VERSION 5.8 ;
BUSBITCHARS "[]" ;
DIVIDERCHAR "/" ;
UNITS
    DATABASE MICRONS 1000 ;
END UNITS

VIA ino_data_cache_via1_2_1000_440_1_2_410_410
  VIARULE via1Array ;
  CUTSIZE 0.19 0.19 ;
  LAYERS Metal1 Via1 Metal2 ;
  CUTSPACING 0.22 0.22 ;
  ENCLOSURE 0.05 0.125 0.005 0.05 ;
  ROWCOL 1 2 ;
END ino_data_cache_via1_2_1000_440_1_2_410_410

VIA ino_data_cache_via2_3_1000_440_1_2_410_410
  VIARULE via2Array ;
  CUTSIZE 0.19 0.19 ;
  LAYERS Metal2 Via2 Metal3 ;
  CUTSPACING 0.22 0.22 ;
  ENCLOSURE 0.005 0.05 0.05 0.005 ;
  ROWCOL 1 2 ;
END ino_data_cache_via2_3_1000_440_1_2_410_410

VIA ino_data_cache_via3_4_1000_440_1_2_410_410
  VIARULE via3Array ;
  CUTSIZE 0.19 0.19 ;
  LAYERS Metal3 Via3 Metal4 ;
  CUTSPACING 0.22 0.22 ;
  ENCLOSURE 0.05 0.005 0.2 0.05 ;
  ROWCOL 1 2 ;
END ino_data_cache_via3_4_1000_440_1_2_410_410

VIA ino_data_cache_via4_5_1000_2000_1_1_840_840
  VIARULE viaTop1Array ;
  CUTSIZE 0.42 0.42 ;
  LAYERS Metal4 TopVia1 TopMetal1 ;
  CUTSPACING 0.42 0.42 ;
  ENCLOSURE 0.29 0.1 0.42 0.79 ;
END ino_data_cache_via4_5_1000_2000_1_1_840_840

VIA ino_data_cache_via4_5_2810_2000_1_2_840_840
  VIARULE viaTop1Array ;
  CUTSIZE 0.42 0.42 ;
  LAYERS Metal4 TopVia1 TopMetal1 ;
  CUTSPACING 0.42 0.42 ;
  ENCLOSURE 0.775 0.79 0.42 0.79 ;
  ROWCOL 1 2 ;
END ino_data_cache_via4_5_2810_2000_1_2_840_840

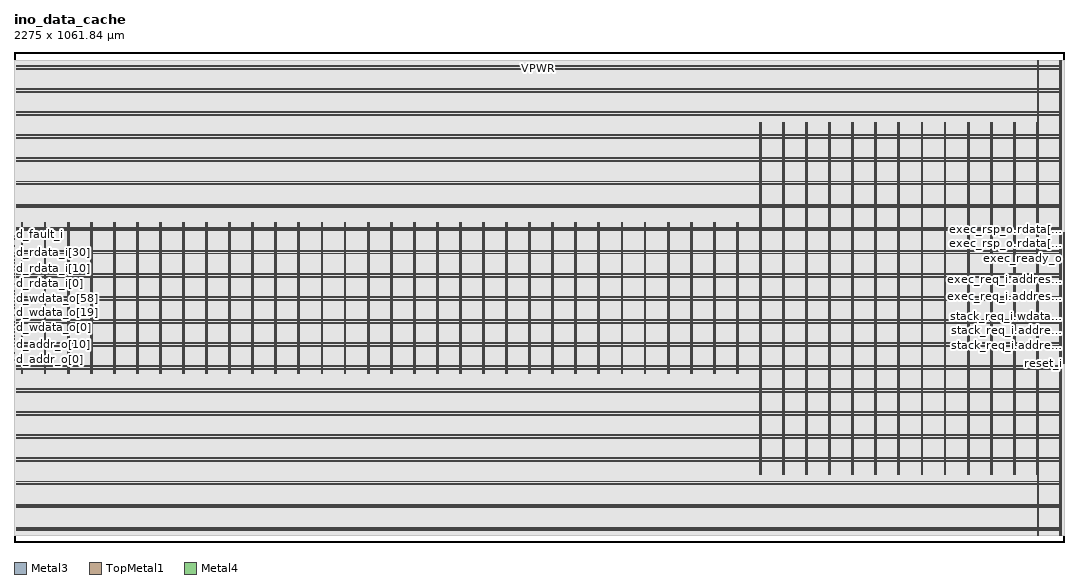
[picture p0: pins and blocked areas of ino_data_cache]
MACRO ino_data_cache
  FOREIGN ino_data_cache 0 0 ;
  CLASS BLOCK ;
  SIZE 2275 BY 1061.84 ;
  PIN clk_i
    DIRECTION INPUT ;
    USE SIGNAL ;
    PORT
      LAYER Metal3 ;
        RECT  2274.6 387.46 2275 387.86 ;
    END
  END clk_i
  PIN d_addr_o[0]
    DIRECTION OUTPUT ;
    USE SIGNAL ;
    PORT
      LAYER Metal3 ;
        RECT  0 394.18 0.4 394.58 ;
    END
  END d_addr_o[0]
  PIN d_addr_o[10]
    DIRECTION OUTPUT ;
    USE SIGNAL ;
    PORT
      LAYER Metal3 ;
        RECT  0 410.98 0.4 411.38 ;
    END
  END d_addr_o[10]
  PIN d_addr_o[11]
    DIRECTION OUTPUT ;
    USE SIGNAL ;
    PORT
      LAYER Metal3 ;
        RECT  0 412.66 0.4 413.06 ;
    END
  END d_addr_o[11]
  PIN d_addr_o[12]
    DIRECTION OUTPUT ;
    USE SIGNAL ;
    PORT
      LAYER Metal3 ;
        RECT  0 414.34 0.4 414.74 ;
    END
  END d_addr_o[12]
  PIN d_addr_o[13]
    DIRECTION OUTPUT ;
    USE SIGNAL ;
    PORT
      LAYER Metal3 ;
        RECT  0 416.02 0.4 416.42 ;
    END
  END d_addr_o[13]
  PIN d_addr_o[14]
    DIRECTION OUTPUT ;
    USE SIGNAL ;
    PORT
      LAYER Metal3 ;
        RECT  0 417.7 0.4 418.1 ;
    END
  END d_addr_o[14]
  PIN d_addr_o[15]
    DIRECTION OUTPUT ;
    USE SIGNAL ;
    PORT
      LAYER Metal3 ;
        RECT  0 419.38 0.4 419.78 ;
    END
  END d_addr_o[15]
  PIN d_addr_o[16]
    DIRECTION OUTPUT ;
    USE SIGNAL ;
    PORT
      LAYER Metal3 ;
        RECT  0 421.06 0.4 421.46 ;
    END
  END d_addr_o[16]
  PIN d_addr_o[17]
    DIRECTION OUTPUT ;
    USE SIGNAL ;
    PORT
      LAYER Metal3 ;
        RECT  0 422.74 0.4 423.14 ;
    END
  END d_addr_o[17]
  PIN d_addr_o[18]
    DIRECTION OUTPUT ;
    USE SIGNAL ;
    PORT
      LAYER Metal3 ;
        RECT  0 424.42 0.4 424.82 ;
    END
  END d_addr_o[18]
  PIN d_addr_o[19]
    DIRECTION OUTPUT ;
    USE SIGNAL ;
    PORT
      LAYER Metal3 ;
        RECT  0 426.1 0.4 426.5 ;
    END
  END d_addr_o[19]
  PIN d_addr_o[1]
    DIRECTION OUTPUT ;
    USE SIGNAL ;
    PORT
      LAYER Metal3 ;
        RECT  0 395.86 0.4 396.26 ;
    END
  END d_addr_o[1]
  PIN d_addr_o[20]
    DIRECTION OUTPUT ;
    USE SIGNAL ;
    PORT
      LAYER Metal3 ;
        RECT  0 427.78 0.4 428.18 ;
    END
  END d_addr_o[20]
  PIN d_addr_o[21]
    DIRECTION OUTPUT ;
    USE SIGNAL ;
    PORT
      LAYER Metal3 ;
        RECT  0 429.46 0.4 429.86 ;
    END
  END d_addr_o[21]
  PIN d_addr_o[22]
    DIRECTION OUTPUT ;
    USE SIGNAL ;
    PORT
      LAYER Metal3 ;
        RECT  0 431.14 0.4 431.54 ;
    END
  END d_addr_o[22]
  PIN d_addr_o[23]
    DIRECTION OUTPUT ;
    USE SIGNAL ;
    PORT
      LAYER Metal3 ;
        RECT  0 432.82 0.4 433.22 ;
    END
  END d_addr_o[23]
  PIN d_addr_o[24]
    DIRECTION OUTPUT ;
    USE SIGNAL ;
    PORT
      LAYER Metal3 ;
        RECT  0 434.5 0.4 434.9 ;
    END
  END d_addr_o[24]
  PIN d_addr_o[25]
    DIRECTION OUTPUT ;
    USE SIGNAL ;
    PORT
      LAYER Metal3 ;
        RECT  0 436.18 0.4 436.58 ;
    END
  END d_addr_o[25]
  PIN d_addr_o[26]
    DIRECTION OUTPUT ;
    USE SIGNAL ;
    PORT
      LAYER Metal3 ;
        RECT  0 437.86 0.4 438.26 ;
    END
  END d_addr_o[26]
  PIN d_addr_o[27]
    DIRECTION OUTPUT ;
    USE SIGNAL ;
    PORT
      LAYER Metal3 ;
        RECT  0 439.54 0.4 439.94 ;
    END
  END d_addr_o[27]
  PIN d_addr_o[28]
    DIRECTION OUTPUT ;
    USE SIGNAL ;
    PORT
      LAYER Metal3 ;
        RECT  0 441.22 0.4 441.62 ;
    END
  END d_addr_o[28]
  PIN d_addr_o[29]
    DIRECTION OUTPUT ;
    USE SIGNAL ;
    PORT
      LAYER Metal3 ;
        RECT  0 442.9 0.4 443.3 ;
    END
  END d_addr_o[29]
  PIN d_addr_o[2]
    DIRECTION OUTPUT ;
    USE SIGNAL ;
    PORT
      LAYER Metal3 ;
        RECT  0 397.54 0.4 397.94 ;
    END
  END d_addr_o[2]
  PIN d_addr_o[30]
    DIRECTION OUTPUT ;
    USE SIGNAL ;
    PORT
      LAYER Metal3 ;
        RECT  0 444.58 0.4 444.98 ;
    END
  END d_addr_o[30]
  PIN d_addr_o[31]
    DIRECTION OUTPUT ;
    USE SIGNAL ;
    PORT
      LAYER Metal3 ;
        RECT  0 446.26 0.4 446.66 ;
    END
  END d_addr_o[31]
  PIN d_addr_o[3]
    DIRECTION OUTPUT ;
    USE SIGNAL ;
    PORT
      LAYER Metal3 ;
        RECT  0 399.22 0.4 399.62 ;
    END
  END d_addr_o[3]
  PIN d_addr_o[4]
    DIRECTION OUTPUT ;
    USE SIGNAL ;
    PORT
      LAYER Metal3 ;
        RECT  0 400.9 0.4 401.3 ;
    END
  END d_addr_o[4]
  PIN d_addr_o[5]
    DIRECTION OUTPUT ;
    USE SIGNAL ;
    PORT
      LAYER Metal3 ;
        RECT  0 402.58 0.4 402.98 ;
    END
  END d_addr_o[5]
  PIN d_addr_o[6]
    DIRECTION OUTPUT ;
    USE SIGNAL ;
    PORT
      LAYER Metal3 ;
        RECT  0 404.26 0.4 404.66 ;
    END
  END d_addr_o[6]
  PIN d_addr_o[7]
    DIRECTION OUTPUT ;
    USE SIGNAL ;
    PORT
      LAYER Metal3 ;
        RECT  0 405.94 0.4 406.34 ;
    END
  END d_addr_o[7]
  PIN d_addr_o[8]
    DIRECTION OUTPUT ;
    USE SIGNAL ;
    PORT
      LAYER Metal3 ;
        RECT  0 407.62 0.4 408.02 ;
    END
  END d_addr_o[8]
  PIN d_addr_o[9]
    DIRECTION OUTPUT ;
    USE SIGNAL ;
    PORT
      LAYER Metal3 ;
        RECT  0 409.3 0.4 409.7 ;
    END
  END d_addr_o[9]
  PIN d_fault_i
    DIRECTION INPUT ;
    USE SIGNAL ;
    PORT
      LAYER Metal3 ;
        RECT  0 666.34 0.4 666.74 ;
    END
  END d_fault_i
  PIN d_rdata_i[0]
    DIRECTION INPUT ;
    USE SIGNAL ;
    PORT
      LAYER Metal3 ;
        RECT  0 558.82 0.4 559.22 ;
    END
  END d_rdata_i[0]
  PIN d_rdata_i[10]
    DIRECTION INPUT ;
    USE SIGNAL ;
    PORT
      LAYER Metal3 ;
        RECT  0 575.62 0.4 576.02 ;
    END
  END d_rdata_i[10]
  PIN d_rdata_i[11]
    DIRECTION INPUT ;
    USE SIGNAL ;
    PORT
      LAYER Metal3 ;
        RECT  0 577.3 0.4 577.7 ;
    END
  END d_rdata_i[11]
  PIN d_rdata_i[12]
    DIRECTION INPUT ;
    USE SIGNAL ;
    PORT
      LAYER Metal3 ;
        RECT  0 578.98 0.4 579.38 ;
    END
  END d_rdata_i[12]
  PIN d_rdata_i[13]
    DIRECTION INPUT ;
    USE SIGNAL ;
    PORT
      LAYER Metal3 ;
        RECT  0 580.66 0.4 581.06 ;
    END
  END d_rdata_i[13]
  PIN d_rdata_i[14]
    DIRECTION INPUT ;
    USE SIGNAL ;
    PORT
      LAYER Metal3 ;
        RECT  0 582.34 0.4 582.74 ;
    END
  END d_rdata_i[14]
  PIN d_rdata_i[15]
    DIRECTION INPUT ;
    USE SIGNAL ;
    PORT
      LAYER Metal3 ;
        RECT  0 584.02 0.4 584.42 ;
    END
  END d_rdata_i[15]
  PIN d_rdata_i[16]
    DIRECTION INPUT ;
    USE SIGNAL ;
    PORT
      LAYER Metal3 ;
        RECT  0 585.7 0.4 586.1 ;
    END
  END d_rdata_i[16]
  PIN d_rdata_i[17]
    DIRECTION INPUT ;
    USE SIGNAL ;
    PORT
      LAYER Metal3 ;
        RECT  0 587.38 0.4 587.78 ;
    END
  END d_rdata_i[17]
  PIN d_rdata_i[18]
    DIRECTION INPUT ;
    USE SIGNAL ;
    PORT
      LAYER Metal3 ;
        RECT  0 589.06 0.4 589.46 ;
    END
  END d_rdata_i[18]
  PIN d_rdata_i[19]
    DIRECTION INPUT ;
    USE SIGNAL ;
    PORT
      LAYER Metal3 ;
        RECT  0 590.74 0.4 591.14 ;
    END
  END d_rdata_i[19]
  PIN d_rdata_i[1]
    DIRECTION INPUT ;
    USE SIGNAL ;
    PORT
      LAYER Metal3 ;
        RECT  0 560.5 0.4 560.9 ;
    END
  END d_rdata_i[1]
  PIN d_rdata_i[20]
    DIRECTION INPUT ;
    USE SIGNAL ;
    PORT
      LAYER Metal3 ;
        RECT  0 592.42 0.4 592.82 ;
    END
  END d_rdata_i[20]
  PIN d_rdata_i[21]
    DIRECTION INPUT ;
    USE SIGNAL ;
    PORT
      LAYER Metal3 ;
        RECT  0 594.1 0.4 594.5 ;
    END
  END d_rdata_i[21]
  PIN d_rdata_i[22]
    DIRECTION INPUT ;
    USE SIGNAL ;
    PORT
      LAYER Metal3 ;
        RECT  0 595.78 0.4 596.18 ;
    END
  END d_rdata_i[22]
  PIN d_rdata_i[23]
    DIRECTION INPUT ;
    USE SIGNAL ;
    PORT
      LAYER Metal3 ;
        RECT  0 597.46 0.4 597.86 ;
    END
  END d_rdata_i[23]
  PIN d_rdata_i[24]
    DIRECTION INPUT ;
    USE SIGNAL ;
    PORT
      LAYER Metal3 ;
        RECT  0 599.14 0.4 599.54 ;
    END
  END d_rdata_i[24]
  PIN d_rdata_i[25]
    DIRECTION INPUT ;
    USE SIGNAL ;
    PORT
      LAYER Metal3 ;
        RECT  0 600.82 0.4 601.22 ;
    END
  END d_rdata_i[25]
  PIN d_rdata_i[26]
    DIRECTION INPUT ;
    USE SIGNAL ;
    PORT
      LAYER Metal3 ;
        RECT  0 602.5 0.4 602.9 ;
    END
  END d_rdata_i[26]
  PIN d_rdata_i[27]
    DIRECTION INPUT ;
    USE SIGNAL ;
    PORT
      LAYER Metal3 ;
        RECT  0 604.18 0.4 604.58 ;
    END
  END d_rdata_i[27]
  PIN d_rdata_i[28]
    DIRECTION INPUT ;
    USE SIGNAL ;
    PORT
      LAYER Metal3 ;
        RECT  0 605.86 0.4 606.26 ;
    END
  END d_rdata_i[28]
  PIN d_rdata_i[29]
    DIRECTION INPUT ;
    USE SIGNAL ;
    PORT
      LAYER Metal3 ;
        RECT  0 607.54 0.4 607.94 ;
    END
  END d_rdata_i[29]
  PIN d_rdata_i[2]
    DIRECTION INPUT ;
    USE SIGNAL ;
    PORT
      LAYER Metal3 ;
        RECT  0 562.18 0.4 562.58 ;
    END
  END d_rdata_i[2]
  PIN d_rdata_i[30]
    DIRECTION INPUT ;
    USE SIGNAL ;
    PORT
      LAYER Metal3 ;
        RECT  0 609.22 0.4 609.62 ;
    END
  END d_rdata_i[30]
  PIN d_rdata_i[31]
    DIRECTION INPUT ;
    USE SIGNAL ;
    PORT
      LAYER Metal3 ;
        RECT  0 610.9 0.4 611.3 ;
    END
  END d_rdata_i[31]
  PIN d_rdata_i[32]
    DIRECTION INPUT ;
    USE SIGNAL ;
    PORT
      LAYER Metal3 ;
        RECT  0 612.58 0.4 612.98 ;
    END
  END d_rdata_i[32]
  PIN d_rdata_i[33]
    DIRECTION INPUT ;
    USE SIGNAL ;
    PORT
      LAYER Metal3 ;
        RECT  0 614.26 0.4 614.66 ;
    END
  END d_rdata_i[33]
  PIN d_rdata_i[34]
    DIRECTION INPUT ;
    USE SIGNAL ;
    PORT
      LAYER Metal3 ;
        RECT  0 615.94 0.4 616.34 ;
    END
  END d_rdata_i[34]
  PIN d_rdata_i[35]
    DIRECTION INPUT ;
    USE SIGNAL ;
    PORT
      LAYER Metal3 ;
        RECT  0 617.62 0.4 618.02 ;
    END
  END d_rdata_i[35]
  PIN d_rdata_i[36]
    DIRECTION INPUT ;
    USE SIGNAL ;
    PORT
      LAYER Metal3 ;
        RECT  0 619.3 0.4 619.7 ;
    END
  END d_rdata_i[36]
  PIN d_rdata_i[37]
    DIRECTION INPUT ;
    USE SIGNAL ;
    PORT
      LAYER Metal3 ;
        RECT  0 620.98 0.4 621.38 ;
    END
  END d_rdata_i[37]
  PIN d_rdata_i[38]
    DIRECTION INPUT ;
    USE SIGNAL ;
    PORT
      LAYER Metal3 ;
        RECT  0 622.66 0.4 623.06 ;
    END
  END d_rdata_i[38]
  PIN d_rdata_i[39]
    DIRECTION INPUT ;
    USE SIGNAL ;
    PORT
      LAYER Metal3 ;
        RECT  0 624.34 0.4 624.74 ;
    END
  END d_rdata_i[39]
  PIN d_rdata_i[3]
    DIRECTION INPUT ;
    USE SIGNAL ;
    PORT
      LAYER Metal3 ;
        RECT  0 563.86 0.4 564.26 ;
    END
  END d_rdata_i[3]
  PIN d_rdata_i[40]
    DIRECTION INPUT ;
    USE SIGNAL ;
    PORT
      LAYER Metal3 ;
        RECT  0 626.02 0.4 626.42 ;
    END
  END d_rdata_i[40]
  PIN d_rdata_i[41]
    DIRECTION INPUT ;
    USE SIGNAL ;
    PORT
      LAYER Metal3 ;
        RECT  0 627.7 0.4 628.1 ;
    END
  END d_rdata_i[41]
  PIN d_rdata_i[42]
    DIRECTION INPUT ;
    USE SIGNAL ;
    PORT
      LAYER Metal3 ;
        RECT  0 629.38 0.4 629.78 ;
    END
  END d_rdata_i[42]
  PIN d_rdata_i[43]
    DIRECTION INPUT ;
    USE SIGNAL ;
    PORT
      LAYER Metal3 ;
        RECT  0 631.06 0.4 631.46 ;
    END
  END d_rdata_i[43]
  PIN d_rdata_i[44]
    DIRECTION INPUT ;
    USE SIGNAL ;
    PORT
      LAYER Metal3 ;
        RECT  0 632.74 0.4 633.14 ;
    END
  END d_rdata_i[44]
  PIN d_rdata_i[45]
    DIRECTION INPUT ;
    USE SIGNAL ;
    PORT
      LAYER Metal3 ;
        RECT  0 634.42 0.4 634.82 ;
    END
  END d_rdata_i[45]
  PIN d_rdata_i[46]
    DIRECTION INPUT ;
    USE SIGNAL ;
    PORT
      LAYER Metal3 ;
        RECT  0 636.1 0.4 636.5 ;
    END
  END d_rdata_i[46]
  PIN d_rdata_i[47]
    DIRECTION INPUT ;
    USE SIGNAL ;
    PORT
      LAYER Metal3 ;
        RECT  0 637.78 0.4 638.18 ;
    END
  END d_rdata_i[47]
  PIN d_rdata_i[48]
    DIRECTION INPUT ;
    USE SIGNAL ;
    PORT
      LAYER Metal3 ;
        RECT  0 639.46 0.4 639.86 ;
    END
  END d_rdata_i[48]
  PIN d_rdata_i[49]
    DIRECTION INPUT ;
    USE SIGNAL ;
    PORT
      LAYER Metal3 ;
        RECT  0 641.14 0.4 641.54 ;
    END
  END d_rdata_i[49]
  PIN d_rdata_i[4]
    DIRECTION INPUT ;
    USE SIGNAL ;
    PORT
      LAYER Metal3 ;
        RECT  0 565.54 0.4 565.94 ;
    END
  END d_rdata_i[4]
  PIN d_rdata_i[50]
    DIRECTION INPUT ;
    USE SIGNAL ;
    PORT
      LAYER Metal3 ;
        RECT  0 642.82 0.4 643.22 ;
    END
  END d_rdata_i[50]
  PIN d_rdata_i[51]
    DIRECTION INPUT ;
    USE SIGNAL ;
    PORT
      LAYER Metal3 ;
        RECT  0 644.5 0.4 644.9 ;
    END
  END d_rdata_i[51]
  PIN d_rdata_i[52]
    DIRECTION INPUT ;
    USE SIGNAL ;
    PORT
      LAYER Metal3 ;
        RECT  0 646.18 0.4 646.58 ;
    END
  END d_rdata_i[52]
  PIN d_rdata_i[53]
    DIRECTION INPUT ;
    USE SIGNAL ;
    PORT
      LAYER Metal3 ;
        RECT  0 647.86 0.4 648.26 ;
    END
  END d_rdata_i[53]
  PIN d_rdata_i[54]
    DIRECTION INPUT ;
    USE SIGNAL ;
    PORT
      LAYER Metal3 ;
        RECT  0 649.54 0.4 649.94 ;
    END
  END d_rdata_i[54]
  PIN d_rdata_i[55]
    DIRECTION INPUT ;
    USE SIGNAL ;
    PORT
      LAYER Metal3 ;
        RECT  0 651.22 0.4 651.62 ;
    END
  END d_rdata_i[55]
  PIN d_rdata_i[56]
    DIRECTION INPUT ;
    USE SIGNAL ;
    PORT
      LAYER Metal3 ;
        RECT  0 652.9 0.4 653.3 ;
    END
  END d_rdata_i[56]
  PIN d_rdata_i[57]
    DIRECTION INPUT ;
    USE SIGNAL ;
    PORT
      LAYER Metal3 ;
        RECT  0 654.58 0.4 654.98 ;
    END
  END d_rdata_i[57]
  PIN d_rdata_i[58]
    DIRECTION INPUT ;
    USE SIGNAL ;
    PORT
      LAYER Metal3 ;
        RECT  0 656.26 0.4 656.66 ;
    END
  END d_rdata_i[58]
  PIN d_rdata_i[59]
    DIRECTION INPUT ;
    USE SIGNAL ;
    PORT
      LAYER Metal3 ;
        RECT  0 657.94 0.4 658.34 ;
    END
  END d_rdata_i[59]
  PIN d_rdata_i[5]
    DIRECTION INPUT ;
    USE SIGNAL ;
    PORT
      LAYER Metal3 ;
        RECT  0 567.22 0.4 567.62 ;
    END
  END d_rdata_i[5]
  PIN d_rdata_i[60]
    DIRECTION INPUT ;
    USE SIGNAL ;
    PORT
      LAYER Metal3 ;
        RECT  0 659.62 0.4 660.02 ;
    END
  END d_rdata_i[60]
  PIN d_rdata_i[61]
    DIRECTION INPUT ;
    USE SIGNAL ;
    PORT
      LAYER Metal3 ;
        RECT  0 661.3 0.4 661.7 ;
    END
  END d_rdata_i[61]
  PIN d_rdata_i[62]
    DIRECTION INPUT ;
    USE SIGNAL ;
    PORT
      LAYER Metal3 ;
        RECT  0 662.98 0.4 663.38 ;
    END
  END d_rdata_i[62]
  PIN d_rdata_i[63]
    DIRECTION INPUT ;
    USE SIGNAL ;
    PORT
      LAYER Metal3 ;
        RECT  0 664.66 0.4 665.06 ;
    END
  END d_rdata_i[63]
  PIN d_rdata_i[6]
    DIRECTION INPUT ;
    USE SIGNAL ;
    PORT
      LAYER Metal3 ;
        RECT  0 568.9 0.4 569.3 ;
    END
  END d_rdata_i[6]
  PIN d_rdata_i[7]
    DIRECTION INPUT ;
    USE SIGNAL ;
    PORT
      LAYER Metal3 ;
        RECT  0 570.58 0.4 570.98 ;
    END
  END d_rdata_i[7]
  PIN d_rdata_i[8]
    DIRECTION INPUT ;
    USE SIGNAL ;
    PORT
      LAYER Metal3 ;
        RECT  0 572.26 0.4 572.66 ;
    END
  END d_rdata_i[8]
  PIN d_rdata_i[9]
    DIRECTION INPUT ;
    USE SIGNAL ;
    PORT
      LAYER Metal3 ;
        RECT  0 573.94 0.4 574.34 ;
    END
  END d_rdata_i[9]
  PIN d_ready_i
    DIRECTION INPUT ;
    USE SIGNAL ;
    PORT
      LAYER Metal3 ;
        RECT  0 555.46 0.4 555.86 ;
    END
  END d_ready_i
  PIN d_req_o
    DIRECTION OUTPUT ;
    USE SIGNAL ;
    PORT
      LAYER Metal3 ;
        RECT  0 390.82 0.4 391.22 ;
    END
  END d_req_o
  PIN d_rvalid_i
    DIRECTION INPUT ;
    USE SIGNAL ;
    PORT
      LAYER Metal3 ;
        RECT  0 557.14 0.4 557.54 ;
    END
  END d_rvalid_i
  PIN d_wdata_o[0]
    DIRECTION OUTPUT ;
    USE SIGNAL ;
    PORT
      LAYER Metal3 ;
        RECT  0 447.94 0.4 448.34 ;
    END
  END d_wdata_o[0]
  PIN d_wdata_o[10]
    DIRECTION OUTPUT ;
    USE SIGNAL ;
    PORT
      LAYER Metal3 ;
        RECT  0 464.74 0.4 465.14 ;
    END
  END d_wdata_o[10]
  PIN d_wdata_o[11]
    DIRECTION OUTPUT ;
    USE SIGNAL ;
    PORT
      LAYER Metal3 ;
        RECT  0 466.42 0.4 466.82 ;
    END
  END d_wdata_o[11]
  PIN d_wdata_o[12]
    DIRECTION OUTPUT ;
    USE SIGNAL ;
    PORT
      LAYER Metal3 ;
        RECT  0 468.1 0.4 468.5 ;
    END
  END d_wdata_o[12]
  PIN d_wdata_o[13]
    DIRECTION OUTPUT ;
    USE SIGNAL ;
    PORT
      LAYER Metal3 ;
        RECT  0 469.78 0.4 470.18 ;
    END
  END d_wdata_o[13]
  PIN d_wdata_o[14]
    DIRECTION OUTPUT ;
    USE SIGNAL ;
    PORT
      LAYER Metal3 ;
        RECT  0 471.46 0.4 471.86 ;
    END
  END d_wdata_o[14]
  PIN d_wdata_o[15]
    DIRECTION OUTPUT ;
    USE SIGNAL ;
    PORT
      LAYER Metal3 ;
        RECT  0 473.14 0.4 473.54 ;
    END
  END d_wdata_o[15]
  PIN d_wdata_o[16]
    DIRECTION OUTPUT ;
    USE SIGNAL ;
    PORT
      LAYER Metal3 ;
        RECT  0 474.82 0.4 475.22 ;
    END
  END d_wdata_o[16]
  PIN d_wdata_o[17]
    DIRECTION OUTPUT ;
    USE SIGNAL ;
    PORT
      LAYER Metal3 ;
        RECT  0 476.5 0.4 476.9 ;
    END
  END d_wdata_o[17]
  PIN d_wdata_o[18]
    DIRECTION OUTPUT ;
    USE SIGNAL ;
    PORT
      LAYER Metal3 ;
        RECT  0 478.18 0.4 478.58 ;
    END
  END d_wdata_o[18]
  PIN d_wdata_o[19]
    DIRECTION OUTPUT ;
    USE SIGNAL ;
    PORT
      LAYER Metal3 ;
        RECT  0 479.86 0.4 480.26 ;
    END
  END d_wdata_o[19]
  PIN d_wdata_o[1]
    DIRECTION OUTPUT ;
    USE SIGNAL ;
    PORT
      LAYER Metal3 ;
        RECT  0 449.62 0.4 450.02 ;
    END
  END d_wdata_o[1]
  PIN d_wdata_o[20]
    DIRECTION OUTPUT ;
    USE SIGNAL ;
    PORT
      LAYER Metal3 ;
        RECT  0 481.54 0.4 481.94 ;
    END
  END d_wdata_o[20]
  PIN d_wdata_o[21]
    DIRECTION OUTPUT ;
    USE SIGNAL ;
    PORT
      LAYER Metal3 ;
        RECT  0 483.22 0.4 483.62 ;
    END
  END d_wdata_o[21]
  PIN d_wdata_o[22]
    DIRECTION OUTPUT ;
    USE SIGNAL ;
    PORT
      LAYER Metal3 ;
        RECT  0 484.9 0.4 485.3 ;
    END
  END d_wdata_o[22]
  PIN d_wdata_o[23]
    DIRECTION OUTPUT ;
    USE SIGNAL ;
    PORT
      LAYER Metal3 ;
        RECT  0 486.58 0.4 486.98 ;
    END
  END d_wdata_o[23]
  PIN d_wdata_o[24]
    DIRECTION OUTPUT ;
    USE SIGNAL ;
    PORT
      LAYER Metal3 ;
        RECT  0 488.26 0.4 488.66 ;
    END
  END d_wdata_o[24]
  PIN d_wdata_o[25]
    DIRECTION OUTPUT ;
    USE SIGNAL ;
    PORT
      LAYER Metal3 ;
        RECT  0 489.94 0.4 490.34 ;
    END
  END d_wdata_o[25]
  PIN d_wdata_o[26]
    DIRECTION OUTPUT ;
    USE SIGNAL ;
    PORT
      LAYER Metal3 ;
        RECT  0 491.62 0.4 492.02 ;
    END
  END d_wdata_o[26]
  PIN d_wdata_o[27]
    DIRECTION OUTPUT ;
    USE SIGNAL ;
    PORT
      LAYER Metal3 ;
        RECT  0 493.3 0.4 493.7 ;
    END
  END d_wdata_o[27]
  PIN d_wdata_o[28]
    DIRECTION OUTPUT ;
    USE SIGNAL ;
    PORT
      LAYER Metal3 ;
        RECT  0 494.98 0.4 495.38 ;
    END
  END d_wdata_o[28]
  PIN d_wdata_o[29]
    DIRECTION OUTPUT ;
    USE SIGNAL ;
    PORT
      LAYER Metal3 ;
        RECT  0 496.66 0.4 497.06 ;
    END
  END d_wdata_o[29]
  PIN d_wdata_o[2]
    DIRECTION OUTPUT ;
    USE SIGNAL ;
    PORT
      LAYER Metal3 ;
        RECT  0 451.3 0.4 451.7 ;
    END
  END d_wdata_o[2]
  PIN d_wdata_o[30]
    DIRECTION OUTPUT ;
    USE SIGNAL ;
    PORT
      LAYER Metal3 ;
        RECT  0 498.34 0.4 498.74 ;
    END
  END d_wdata_o[30]
  PIN d_wdata_o[31]
    DIRECTION OUTPUT ;
    USE SIGNAL ;
    PORT
      LAYER Metal3 ;
        RECT  0 500.02 0.4 500.42 ;
    END
  END d_wdata_o[31]
  PIN d_wdata_o[32]
    DIRECTION OUTPUT ;
    USE SIGNAL ;
    PORT
      LAYER Metal3 ;
        RECT  0 501.7 0.4 502.1 ;
    END
  END d_wdata_o[32]
  PIN d_wdata_o[33]
    DIRECTION OUTPUT ;
    USE SIGNAL ;
    PORT
      LAYER Metal3 ;
        RECT  0 503.38 0.4 503.78 ;
    END
  END d_wdata_o[33]
  PIN d_wdata_o[34]
    DIRECTION OUTPUT ;
    USE SIGNAL ;
    PORT
      LAYER Metal3 ;
        RECT  0 505.06 0.4 505.46 ;
    END
  END d_wdata_o[34]
  PIN d_wdata_o[35]
    DIRECTION OUTPUT ;
    USE SIGNAL ;
    PORT
      LAYER Metal3 ;
        RECT  0 506.74 0.4 507.14 ;
    END
  END d_wdata_o[35]
  PIN d_wdata_o[36]
    DIRECTION OUTPUT ;
    USE SIGNAL ;
    PORT
      LAYER Metal3 ;
        RECT  0 508.42 0.4 508.82 ;
    END
  END d_wdata_o[36]
  PIN d_wdata_o[37]
    DIRECTION OUTPUT ;
    USE SIGNAL ;
    PORT
      LAYER Metal3 ;
        RECT  0 510.1 0.4 510.5 ;
    END
  END d_wdata_o[37]
  PIN d_wdata_o[38]
    DIRECTION OUTPUT ;
    USE SIGNAL ;
    PORT
      LAYER Metal3 ;
        RECT  0 511.78 0.4 512.18 ;
    END
  END d_wdata_o[38]
  PIN d_wdata_o[39]
    DIRECTION OUTPUT ;
    USE SIGNAL ;
    PORT
      LAYER Metal3 ;
        RECT  0 513.46 0.4 513.86 ;
    END
  END d_wdata_o[39]
  PIN d_wdata_o[3]
    DIRECTION OUTPUT ;
    USE SIGNAL ;
    PORT
      LAYER Metal3 ;
        RECT  0 452.98 0.4 453.38 ;
    END
  END d_wdata_o[3]
  PIN d_wdata_o[40]
    DIRECTION OUTPUT ;
    USE SIGNAL ;
    PORT
      LAYER Metal3 ;
        RECT  0 515.14 0.4 515.54 ;
    END
  END d_wdata_o[40]
  PIN d_wdata_o[41]
    DIRECTION OUTPUT ;
    USE SIGNAL ;
    PORT
      LAYER Metal3 ;
        RECT  0 516.82 0.4 517.22 ;
    END
  END d_wdata_o[41]
  PIN d_wdata_o[42]
    DIRECTION OUTPUT ;
    USE SIGNAL ;
    PORT
      LAYER Metal3 ;
        RECT  0 518.5 0.4 518.9 ;
    END
  END d_wdata_o[42]
  PIN d_wdata_o[43]
    DIRECTION OUTPUT ;
    USE SIGNAL ;
    PORT
      LAYER Metal3 ;
        RECT  0 520.18 0.4 520.58 ;
    END
  END d_wdata_o[43]
  PIN d_wdata_o[44]
    DIRECTION OUTPUT ;
    USE SIGNAL ;
    PORT
      LAYER Metal3 ;
        RECT  0 521.86 0.4 522.26 ;
    END
  END d_wdata_o[44]
  PIN d_wdata_o[45]
    DIRECTION OUTPUT ;
    USE SIGNAL ;
    PORT
      LAYER Metal3 ;
        RECT  0 523.54 0.4 523.94 ;
    END
  END d_wdata_o[45]
  PIN d_wdata_o[46]
    DIRECTION OUTPUT ;
    USE SIGNAL ;
    PORT
      LAYER Metal3 ;
        RECT  0 525.22 0.4 525.62 ;
    END
  END d_wdata_o[46]
  PIN d_wdata_o[47]
    DIRECTION OUTPUT ;
    USE SIGNAL ;
    PORT
      LAYER Metal3 ;
        RECT  0 526.9 0.4 527.3 ;
    END
  END d_wdata_o[47]
  PIN d_wdata_o[48]
    DIRECTION OUTPUT ;
    USE SIGNAL ;
    PORT
      LAYER Metal3 ;
        RECT  0 528.58 0.4 528.98 ;
    END
  END d_wdata_o[48]
  PIN d_wdata_o[49]
    DIRECTION OUTPUT ;
    USE SIGNAL ;
    PORT
      LAYER Metal3 ;
        RECT  0 530.26 0.4 530.66 ;
    END
  END d_wdata_o[49]
  PIN d_wdata_o[4]
    DIRECTION OUTPUT ;
    USE SIGNAL ;
    PORT
      LAYER Metal3 ;
        RECT  0 454.66 0.4 455.06 ;
    END
  END d_wdata_o[4]
  PIN d_wdata_o[50]
    DIRECTION OUTPUT ;
    USE SIGNAL ;
    PORT
      LAYER Metal3 ;
        RECT  0 531.94 0.4 532.34 ;
    END
  END d_wdata_o[50]
  PIN d_wdata_o[51]
    DIRECTION OUTPUT ;
    USE SIGNAL ;
    PORT
      LAYER Metal3 ;
        RECT  0 533.62 0.4 534.02 ;
    END
  END d_wdata_o[51]
  PIN d_wdata_o[52]
    DIRECTION OUTPUT ;
    USE SIGNAL ;
    PORT
      LAYER Metal3 ;
        RECT  0 535.3 0.4 535.7 ;
    END
  END d_wdata_o[52]
  PIN d_wdata_o[53]
    DIRECTION OUTPUT ;
    USE SIGNAL ;
    PORT
      LAYER Metal3 ;
        RECT  0 536.98 0.4 537.38 ;
    END
  END d_wdata_o[53]
  PIN d_wdata_o[54]
    DIRECTION OUTPUT ;
    USE SIGNAL ;
    PORT
      LAYER Metal3 ;
        RECT  0 538.66 0.4 539.06 ;
    END
  END d_wdata_o[54]
  PIN d_wdata_o[55]
    DIRECTION OUTPUT ;
    USE SIGNAL ;
    PORT
      LAYER Metal3 ;
        RECT  0 540.34 0.4 540.74 ;
    END
  END d_wdata_o[55]
  PIN d_wdata_o[56]
    DIRECTION OUTPUT ;
    USE SIGNAL ;
    PORT
      LAYER Metal3 ;
        RECT  0 542.02 0.4 542.42 ;
    END
  END d_wdata_o[56]
  PIN d_wdata_o[57]
    DIRECTION OUTPUT ;
    USE SIGNAL ;
    PORT
      LAYER Metal3 ;
        RECT  0 543.7 0.4 544.1 ;
    END
  END d_wdata_o[57]
  PIN d_wdata_o[58]
    DIRECTION OUTPUT ;
    USE SIGNAL ;
    PORT
      LAYER Metal3 ;
        RECT  0 545.38 0.4 545.78 ;
    END
  END d_wdata_o[58]
  PIN d_wdata_o[59]
    DIRECTION OUTPUT ;
    USE SIGNAL ;
    PORT
      LAYER Metal3 ;
        RECT  0 547.06 0.4 547.46 ;
    END
  END d_wdata_o[59]
  PIN d_wdata_o[5]
    DIRECTION OUTPUT ;
    USE SIGNAL ;
    PORT
      LAYER Metal3 ;
        RECT  0 456.34 0.4 456.74 ;
    END
  END d_wdata_o[5]
  PIN d_wdata_o[60]
    DIRECTION OUTPUT ;
    USE SIGNAL ;
    PORT
      LAYER Metal3 ;
        RECT  0 548.74 0.4 549.14 ;
    END
  END d_wdata_o[60]
  PIN d_wdata_o[61]
    DIRECTION OUTPUT ;
    USE SIGNAL ;
    PORT
      LAYER Metal3 ;
        RECT  0 550.42 0.4 550.82 ;
    END
  END d_wdata_o[61]
  PIN d_wdata_o[62]
    DIRECTION OUTPUT ;
    USE SIGNAL ;
    PORT
      LAYER Metal3 ;
        RECT  0 552.1 0.4 552.5 ;
    END
  END d_wdata_o[62]
  PIN d_wdata_o[63]
    DIRECTION OUTPUT ;
    USE SIGNAL ;
    PORT
      LAYER Metal3 ;
        RECT  0 553.78 0.4 554.18 ;
    END
  END d_wdata_o[63]
  PIN d_wdata_o[6]
    DIRECTION OUTPUT ;
    USE SIGNAL ;
    PORT
      LAYER Metal3 ;
        RECT  0 458.02 0.4 458.42 ;
    END
  END d_wdata_o[6]
  PIN d_wdata_o[7]
    DIRECTION OUTPUT ;
    USE SIGNAL ;
    PORT
      LAYER Metal3 ;
        RECT  0 459.7 0.4 460.1 ;
    END
  END d_wdata_o[7]
  PIN d_wdata_o[8]
    DIRECTION OUTPUT ;
    USE SIGNAL ;
    PORT
      LAYER Metal3 ;
        RECT  0 461.38 0.4 461.78 ;
    END
  END d_wdata_o[8]
  PIN d_wdata_o[9]
    DIRECTION OUTPUT ;
    USE SIGNAL ;
    PORT
      LAYER Metal3 ;
        RECT  0 463.06 0.4 463.46 ;
    END
  END d_wdata_o[9]
  PIN d_write_o
    DIRECTION OUTPUT ;
    USE SIGNAL ;
    PORT
      LAYER Metal3 ;
        RECT  0 392.5 0.4 392.9 ;
    END
  END d_write_o
  PIN exec_ready_o
    DIRECTION OUTPUT ;
    USE SIGNAL ;
    PORT
      LAYER Metal3 ;
        RECT  2274.6 615.1 2275 615.5 ;
    END
  END exec_ready_o
  PIN exec_req_i.address[0]
    DIRECTION INPUT ;
    USE SIGNAL ;
    PORT
      LAYER Metal3 ;
        RECT  2274.6 532.78 2275 533.18 ;
    END
  END exec_req_i.address[0]
  PIN exec_req_i.address[10]
    DIRECTION INPUT ;
    USE SIGNAL ;
    PORT
      LAYER Metal3 ;
        RECT  2274.6 551.26 2275 551.66 ;
    END
  END exec_req_i.address[10]
  PIN exec_req_i.address[11]
    DIRECTION INPUT ;
    USE SIGNAL ;
    PORT
      LAYER Metal3 ;
        RECT  2274.6 552.94 2275 553.34 ;
    END
  END exec_req_i.address[11]
  PIN exec_req_i.address[12]
    DIRECTION INPUT ;
    USE SIGNAL ;
    PORT
      LAYER Metal3 ;
        RECT  2274.6 554.62 2275 555.02 ;
    END
  END exec_req_i.address[12]
  PIN exec_req_i.address[13]
    DIRECTION INPUT ;
    USE SIGNAL ;
    PORT
      LAYER Metal3 ;
        RECT  2274.6 556.3 2275 556.7 ;
    END
  END exec_req_i.address[13]
  PIN exec_req_i.address[14]
    DIRECTION INPUT ;
    USE SIGNAL ;
    PORT
      LAYER Metal3 ;
        RECT  2274.6 557.98 2275 558.38 ;
    END
  END exec_req_i.address[14]
  PIN exec_req_i.address[15]
    DIRECTION INPUT ;
    USE SIGNAL ;
    PORT
      LAYER Metal3 ;
        RECT  2274.6 559.66 2275 560.06 ;
    END
  END exec_req_i.address[15]
  PIN exec_req_i.address[16]
    DIRECTION INPUT ;
    USE SIGNAL ;
    PORT
      LAYER Metal3 ;
        RECT  2274.6 561.34 2275 561.74 ;
    END
  END exec_req_i.address[16]
  PIN exec_req_i.address[17]
    DIRECTION INPUT ;
    USE SIGNAL ;
    PORT
      LAYER Metal3 ;
        RECT  2274.6 563.02 2275 563.42 ;
    END
  END exec_req_i.address[17]
  PIN exec_req_i.address[18]
    DIRECTION INPUT ;
    USE SIGNAL ;
    PORT
      LAYER Metal3 ;
        RECT  2274.6 564.7 2275 565.1 ;
    END
  END exec_req_i.address[18]
  PIN exec_req_i.address[19]
    DIRECTION INPUT ;
    USE SIGNAL ;
    PORT
      LAYER Metal3 ;
        RECT  2274.6 566.38 2275 566.78 ;
    END
  END exec_req_i.address[19]
  PIN exec_req_i.address[1]
    DIRECTION INPUT ;
    USE SIGNAL ;
    PORT
      LAYER Metal3 ;
        RECT  2274.6 535.3 2275 535.7 ;
    END
  END exec_req_i.address[1]
  PIN exec_req_i.address[20]
    DIRECTION INPUT ;
    USE SIGNAL ;
    PORT
      LAYER Metal3 ;
        RECT  2274.6 568.06 2275 568.46 ;
    END
  END exec_req_i.address[20]
  PIN exec_req_i.address[21]
    DIRECTION INPUT ;
    USE SIGNAL ;
    PORT
      LAYER Metal3 ;
        RECT  2274.6 569.74 2275 570.14 ;
    END
  END exec_req_i.address[21]
  PIN exec_req_i.address[22]
    DIRECTION INPUT ;
    USE SIGNAL ;
    PORT
      LAYER Metal3 ;
        RECT  2274.6 571.42 2275 571.82 ;
    END
  END exec_req_i.address[22]
  PIN exec_req_i.address[23]
    DIRECTION INPUT ;
    USE SIGNAL ;
    PORT
      LAYER Metal3 ;
        RECT  2274.6 573.1 2275 573.5 ;
    END
  END exec_req_i.address[23]
  PIN exec_req_i.address[24]
    DIRECTION INPUT ;
    USE SIGNAL ;
    PORT
      LAYER Metal3 ;
        RECT  2274.6 574.78 2275 575.18 ;
    END
  END exec_req_i.address[24]
  PIN exec_req_i.address[25]
    DIRECTION INPUT ;
    USE SIGNAL ;
    PORT
      LAYER Metal3 ;
        RECT  2274.6 576.46 2275 576.86 ;
    END
  END exec_req_i.address[25]
  PIN exec_req_i.address[26]
    DIRECTION INPUT ;
    USE SIGNAL ;
    PORT
      LAYER Metal3 ;
        RECT  2274.6 578.14 2275 578.54 ;
    END
  END exec_req_i.address[26]
  PIN exec_req_i.address[27]
    DIRECTION INPUT ;
    USE SIGNAL ;
    PORT
      LAYER Metal3 ;
        RECT  2274.6 579.82 2275 580.22 ;
    END
  END exec_req_i.address[27]
  PIN exec_req_i.address[28]
    DIRECTION INPUT ;
    USE SIGNAL ;
    PORT
      LAYER Metal3 ;
        RECT  2274.6 581.5 2275 581.9 ;
    END
  END exec_req_i.address[28]
  PIN exec_req_i.address[29]
    DIRECTION INPUT ;
    USE SIGNAL ;
    PORT
      LAYER Metal3 ;
        RECT  2274.6 583.18 2275 583.58 ;
    END
  END exec_req_i.address[29]
  PIN exec_req_i.address[2]
    DIRECTION INPUT ;
    USE SIGNAL ;
    PORT
      LAYER Metal3 ;
        RECT  2274.6 537.82 2275 538.22 ;
    END
  END exec_req_i.address[2]
  PIN exec_req_i.address[30]
    DIRECTION INPUT ;
    USE SIGNAL ;
    PORT
      LAYER Metal3 ;
        RECT  2274.6 584.86 2275 585.26 ;
    END
  END exec_req_i.address[30]
  PIN exec_req_i.address[31]
    DIRECTION INPUT ;
    USE SIGNAL ;
    PORT
      LAYER Metal3 ;
        RECT  2274.6 586.54 2275 586.94 ;
    END
  END exec_req_i.address[31]
  PIN exec_req_i.address[3]
    DIRECTION INPUT ;
    USE SIGNAL ;
    PORT
      LAYER Metal3 ;
        RECT  2274.6 539.5 2275 539.9 ;
    END
  END exec_req_i.address[3]
  PIN exec_req_i.address[4]
    DIRECTION INPUT ;
    USE SIGNAL ;
    PORT
      LAYER Metal3 ;
        RECT  2274.6 541.18 2275 541.58 ;
    END
  END exec_req_i.address[4]
  PIN exec_req_i.address[5]
    DIRECTION INPUT ;
    USE SIGNAL ;
    PORT
      LAYER Metal3 ;
        RECT  2274.6 542.86 2275 543.26 ;
    END
  END exec_req_i.address[5]
  PIN exec_req_i.address[6]
    DIRECTION INPUT ;
    USE SIGNAL ;
    PORT
      LAYER Metal3 ;
        RECT  2274.6 544.54 2275 544.94 ;
    END
  END exec_req_i.address[6]
  PIN exec_req_i.address[7]
    DIRECTION INPUT ;
    USE SIGNAL ;
    PORT
      LAYER Metal3 ;
        RECT  2274.6 546.22 2275 546.62 ;
    END
  END exec_req_i.address[7]
  PIN exec_req_i.address[8]
    DIRECTION INPUT ;
    USE SIGNAL ;
    PORT
      LAYER Metal3 ;
        RECT  2274.6 547.9 2275 548.3 ;
    END
  END exec_req_i.address[8]
  PIN exec_req_i.address[9]
    DIRECTION INPUT ;
    USE SIGNAL ;
    PORT
      LAYER Metal3 ;
        RECT  2274.6 549.58 2275 549.98 ;
    END
  END exec_req_i.address[9]
  PIN exec_req_i.outside
    DIRECTION INPUT ;
    USE SIGNAL ;
    PORT
      LAYER Metal3 ;
        RECT  2274.6 529.42 2275 529.82 ;
    END
  END exec_req_i.outside
  PIN exec_req_i.probe
    DIRECTION INPUT ;
    USE SIGNAL ;
    PORT
      LAYER Metal3 ;
        RECT  2274.6 530.26 2275 530.66 ;
    END
  END exec_req_i.probe
  PIN exec_req_i.size[0]
    DIRECTION INPUT ;
    USE SIGNAL ;
    PORT
      LAYER Metal3 ;
        RECT  2274.6 533.62 2275 534.02 ;
    END
  END exec_req_i.size[0]
  PIN exec_req_i.size[1]
    DIRECTION INPUT ;
    USE SIGNAL ;
    PORT
      LAYER Metal3 ;
        RECT  2274.6 536.14 2275 536.54 ;
    END
  END exec_req_i.size[1]
  PIN exec_req_i.valid
    DIRECTION INPUT ;
    USE SIGNAL ;
    PORT
      LAYER Metal3 ;
        RECT  2274.6 531.1 2275 531.5 ;
    END
  END exec_req_i.valid
  PIN exec_req_i.wdata[0]
    DIRECTION INPUT ;
    USE SIGNAL ;
    PORT
      LAYER Metal3 ;
        RECT  2274.6 534.46 2275 534.86 ;
    END
  END exec_req_i.wdata[0]
  PIN exec_req_i.wdata[10]
    DIRECTION INPUT ;
    USE SIGNAL ;
    PORT
      LAYER Metal3 ;
        RECT  2274.6 552.1 2275 552.5 ;
    END
  END exec_req_i.wdata[10]
  PIN exec_req_i.wdata[11]
    DIRECTION INPUT ;
    USE SIGNAL ;
    PORT
      LAYER Metal3 ;
        RECT  2274.6 553.78 2275 554.18 ;
    END
  END exec_req_i.wdata[11]
  PIN exec_req_i.wdata[12]
    DIRECTION INPUT ;
    USE SIGNAL ;
    PORT
      LAYER Metal3 ;
        RECT  2274.6 555.46 2275 555.86 ;
    END
  END exec_req_i.wdata[12]
  PIN exec_req_i.wdata[13]
    DIRECTION INPUT ;
    USE SIGNAL ;
    PORT
      LAYER Metal3 ;
        RECT  2274.6 557.14 2275 557.54 ;
    END
  END exec_req_i.wdata[13]
  PIN exec_req_i.wdata[14]
    DIRECTION INPUT ;
    USE SIGNAL ;
    PORT
      LAYER Metal3 ;
        RECT  2274.6 558.82 2275 559.22 ;
    END
  END exec_req_i.wdata[14]
  PIN exec_req_i.wdata[15]
    DIRECTION INPUT ;
    USE SIGNAL ;
    PORT
      LAYER Metal3 ;
        RECT  2274.6 560.5 2275 560.9 ;
    END
  END exec_req_i.wdata[15]
  PIN exec_req_i.wdata[16]
    DIRECTION INPUT ;
    USE SIGNAL ;
    PORT
      LAYER Metal3 ;
        RECT  2274.6 562.18 2275 562.58 ;
    END
  END exec_req_i.wdata[16]
  PIN exec_req_i.wdata[17]
    DIRECTION INPUT ;
    USE SIGNAL ;
    PORT
      LAYER Metal3 ;
        RECT  2274.6 563.86 2275 564.26 ;
    END
  END exec_req_i.wdata[17]
  PIN exec_req_i.wdata[18]
    DIRECTION INPUT ;
    USE SIGNAL ;
    PORT
      LAYER Metal3 ;
        RECT  2274.6 565.54 2275 565.94 ;
    END
  END exec_req_i.wdata[18]
  PIN exec_req_i.wdata[19]
    DIRECTION INPUT ;
    USE SIGNAL ;
    PORT
      LAYER Metal3 ;
        RECT  2274.6 567.22 2275 567.62 ;
    END
  END exec_req_i.wdata[19]
  PIN exec_req_i.wdata[1]
    DIRECTION INPUT ;
    USE SIGNAL ;
    PORT
      LAYER Metal3 ;
        RECT  2274.6 536.98 2275 537.38 ;
    END
  END exec_req_i.wdata[1]
  PIN exec_req_i.wdata[20]
    DIRECTION INPUT ;
    USE SIGNAL ;
    PORT
      LAYER Metal3 ;
        RECT  2274.6 568.9 2275 569.3 ;
    END
  END exec_req_i.wdata[20]
  PIN exec_req_i.wdata[21]
    DIRECTION INPUT ;
    USE SIGNAL ;
    PORT
      LAYER Metal3 ;
        RECT  2274.6 570.58 2275 570.98 ;
    END
  END exec_req_i.wdata[21]
  PIN exec_req_i.wdata[22]
    DIRECTION INPUT ;
    USE SIGNAL ;
    PORT
      LAYER Metal3 ;
        RECT  2274.6 572.26 2275 572.66 ;
    END
  END exec_req_i.wdata[22]
  PIN exec_req_i.wdata[23]
    DIRECTION INPUT ;
    USE SIGNAL ;
    PORT
      LAYER Metal3 ;
        RECT  2274.6 573.94 2275 574.34 ;
    END
  END exec_req_i.wdata[23]
  PIN exec_req_i.wdata[24]
    DIRECTION INPUT ;
    USE SIGNAL ;
    PORT
      LAYER Metal3 ;
        RECT  2274.6 575.62 2275 576.02 ;
    END
  END exec_req_i.wdata[24]
  PIN exec_req_i.wdata[25]
    DIRECTION INPUT ;
    USE SIGNAL ;
    PORT
      LAYER Metal3 ;
        RECT  2274.6 577.3 2275 577.7 ;
    END
  END exec_req_i.wdata[25]
  PIN exec_req_i.wdata[26]
    DIRECTION INPUT ;
    USE SIGNAL ;
    PORT
      LAYER Metal3 ;
        RECT  2274.6 578.98 2275 579.38 ;
    END
  END exec_req_i.wdata[26]
  PIN exec_req_i.wdata[27]
    DIRECTION INPUT ;
    USE SIGNAL ;
    PORT
      LAYER Metal3 ;
        RECT  2274.6 580.66 2275 581.06 ;
    END
  END exec_req_i.wdata[27]
  PIN exec_req_i.wdata[28]
    DIRECTION INPUT ;
    USE SIGNAL ;
    PORT
      LAYER Metal3 ;
        RECT  2274.6 582.34 2275 582.74 ;
    END
  END exec_req_i.wdata[28]
  PIN exec_req_i.wdata[29]
    DIRECTION INPUT ;
    USE SIGNAL ;
    PORT
      LAYER Metal3 ;
        RECT  2274.6 584.02 2275 584.42 ;
    END
  END exec_req_i.wdata[29]
  PIN exec_req_i.wdata[2]
    DIRECTION INPUT ;
    USE SIGNAL ;
    PORT
      LAYER Metal3 ;
        RECT  2274.6 538.66 2275 539.06 ;
    END
  END exec_req_i.wdata[2]
  PIN exec_req_i.wdata[30]
    DIRECTION INPUT ;
    USE SIGNAL ;
    PORT
      LAYER Metal3 ;
        RECT  2274.6 585.7 2275 586.1 ;
    END
  END exec_req_i.wdata[30]
  PIN exec_req_i.wdata[31]
    DIRECTION INPUT ;
    USE SIGNAL ;
    PORT
      LAYER Metal3 ;
        RECT  2274.6 587.38 2275 587.78 ;
    END
  END exec_req_i.wdata[31]
  PIN exec_req_i.wdata[32]
    DIRECTION INPUT ;
    USE SIGNAL ;
    PORT
      LAYER Metal3 ;
        RECT  2274.6 588.22 2275 588.62 ;
    END
  END exec_req_i.wdata[32]
  PIN exec_req_i.wdata[33]
    DIRECTION INPUT ;
    USE SIGNAL ;
    PORT
      LAYER Metal3 ;
        RECT  2274.6 589.06 2275 589.46 ;
    END
  END exec_req_i.wdata[33]
  PIN exec_req_i.wdata[34]
    DIRECTION INPUT ;
    USE SIGNAL ;
    PORT
      LAYER Metal3 ;
        RECT  2274.6 589.9 2275 590.3 ;
    END
  END exec_req_i.wdata[34]
  PIN exec_req_i.wdata[35]
    DIRECTION INPUT ;
    USE SIGNAL ;
    PORT
      LAYER Metal3 ;
        RECT  2274.6 590.74 2275 591.14 ;
    END
  END exec_req_i.wdata[35]
  PIN exec_req_i.wdata[36]
    DIRECTION INPUT ;
    USE SIGNAL ;
    PORT
      LAYER Metal3 ;
        RECT  2274.6 591.58 2275 591.98 ;
    END
  END exec_req_i.wdata[36]
  PIN exec_req_i.wdata[37]
    DIRECTION INPUT ;
    USE SIGNAL ;
    PORT
      LAYER Metal3 ;
        RECT  2274.6 592.42 2275 592.82 ;
    END
  END exec_req_i.wdata[37]
  PIN exec_req_i.wdata[38]
    DIRECTION INPUT ;
    USE SIGNAL ;
    PORT
      LAYER Metal3 ;
        RECT  2274.6 593.26 2275 593.66 ;
    END
  END exec_req_i.wdata[38]
  PIN exec_req_i.wdata[39]
    DIRECTION INPUT ;
    USE SIGNAL ;
    PORT
      LAYER Metal3 ;
        RECT  2274.6 594.1 2275 594.5 ;
    END
  END exec_req_i.wdata[39]
  PIN exec_req_i.wdata[3]
    DIRECTION INPUT ;
    USE SIGNAL ;
    PORT
      LAYER Metal3 ;
        RECT  2274.6 540.34 2275 540.74 ;
    END
  END exec_req_i.wdata[3]
  PIN exec_req_i.wdata[40]
    DIRECTION INPUT ;
    USE SIGNAL ;
    PORT
      LAYER Metal3 ;
        RECT  2274.6 594.94 2275 595.34 ;
    END
  END exec_req_i.wdata[40]
  PIN exec_req_i.wdata[41]
    DIRECTION INPUT ;
    USE SIGNAL ;
    PORT
      LAYER Metal3 ;
        RECT  2274.6 595.78 2275 596.18 ;
    END
  END exec_req_i.wdata[41]
  PIN exec_req_i.wdata[42]
    DIRECTION INPUT ;
    USE SIGNAL ;
    PORT
      LAYER Metal3 ;
        RECT  2274.6 596.62 2275 597.02 ;
    END
  END exec_req_i.wdata[42]
  PIN exec_req_i.wdata[43]
    DIRECTION INPUT ;
    USE SIGNAL ;
    PORT
      LAYER Metal3 ;
        RECT  2274.6 597.46 2275 597.86 ;
    END
  END exec_req_i.wdata[43]
  PIN exec_req_i.wdata[44]
    DIRECTION INPUT ;
    USE SIGNAL ;
    PORT
      LAYER Metal3 ;
        RECT  2274.6 598.3 2275 598.7 ;
    END
  END exec_req_i.wdata[44]
  PIN exec_req_i.wdata[45]
    DIRECTION INPUT ;
    USE SIGNAL ;
    PORT
      LAYER Metal3 ;
        RECT  2274.6 599.14 2275 599.54 ;
    END
  END exec_req_i.wdata[45]
  PIN exec_req_i.wdata[46]
    DIRECTION INPUT ;
    USE SIGNAL ;
    PORT
      LAYER Metal3 ;
        RECT  2274.6 599.98 2275 600.38 ;
    END
  END exec_req_i.wdata[46]
  PIN exec_req_i.wdata[47]
    DIRECTION INPUT ;
    USE SIGNAL ;
    PORT
      LAYER Metal3 ;
        RECT  2274.6 600.82 2275 601.22 ;
    END
  END exec_req_i.wdata[47]
  PIN exec_req_i.wdata[48]
    DIRECTION INPUT ;
    USE SIGNAL ;
    PORT
      LAYER Metal3 ;
        RECT  2274.6 601.66 2275 602.06 ;
    END
  END exec_req_i.wdata[48]
  PIN exec_req_i.wdata[49]
    DIRECTION INPUT ;
    USE SIGNAL ;
    PORT
      LAYER Metal3 ;
        RECT  2274.6 602.5 2275 602.9 ;
    END
  END exec_req_i.wdata[49]
  PIN exec_req_i.wdata[4]
    DIRECTION INPUT ;
    USE SIGNAL ;
    PORT
      LAYER Metal3 ;
        RECT  2274.6 542.02 2275 542.42 ;
    END
  END exec_req_i.wdata[4]
  PIN exec_req_i.wdata[50]
    DIRECTION INPUT ;
    USE SIGNAL ;
    PORT
      LAYER Metal3 ;
        RECT  2274.6 603.34 2275 603.74 ;
    END
  END exec_req_i.wdata[50]
  PIN exec_req_i.wdata[51]
    DIRECTION INPUT ;
    USE SIGNAL ;
    PORT
      LAYER Metal3 ;
        RECT  2274.6 604.18 2275 604.58 ;
    END
  END exec_req_i.wdata[51]
  PIN exec_req_i.wdata[52]
    DIRECTION INPUT ;
    USE SIGNAL ;
    PORT
      LAYER Metal3 ;
        RECT  2274.6 605.02 2275 605.42 ;
    END
  END exec_req_i.wdata[52]
  PIN exec_req_i.wdata[53]
    DIRECTION INPUT ;
    USE SIGNAL ;
    PORT
      LAYER Metal3 ;
        RECT  2274.6 605.86 2275 606.26 ;
    END
  END exec_req_i.wdata[53]
  PIN exec_req_i.wdata[54]
    DIRECTION INPUT ;
    USE SIGNAL ;
    PORT
      LAYER Metal3 ;
        RECT  2274.6 606.7 2275 607.1 ;
    END
  END exec_req_i.wdata[54]
  PIN exec_req_i.wdata[55]
    DIRECTION INPUT ;
    USE SIGNAL ;
    PORT
      LAYER Metal3 ;
        RECT  2274.6 607.54 2275 607.94 ;
    END
  END exec_req_i.wdata[55]
  PIN exec_req_i.wdata[56]
    DIRECTION INPUT ;
    USE SIGNAL ;
    PORT
      LAYER Metal3 ;
        RECT  2274.6 608.38 2275 608.78 ;
    END
  END exec_req_i.wdata[56]
  PIN exec_req_i.wdata[57]
    DIRECTION INPUT ;
    USE SIGNAL ;
    PORT
      LAYER Metal3 ;
        RECT  2274.6 609.22 2275 609.62 ;
    END
  END exec_req_i.wdata[57]
  PIN exec_req_i.wdata[58]
    DIRECTION INPUT ;
    USE SIGNAL ;
    PORT
      LAYER Metal3 ;
        RECT  2274.6 610.06 2275 610.46 ;
    END
  END exec_req_i.wdata[58]
  PIN exec_req_i.wdata[59]
    DIRECTION INPUT ;
    USE SIGNAL ;
    PORT
      LAYER Metal3 ;
        RECT  2274.6 610.9 2275 611.3 ;
    END
  END exec_req_i.wdata[59]
  PIN exec_req_i.wdata[5]
    DIRECTION INPUT ;
    USE SIGNAL ;
    PORT
      LAYER Metal3 ;
        RECT  2274.6 543.7 2275 544.1 ;
    END
  END exec_req_i.wdata[5]
  PIN exec_req_i.wdata[60]
    DIRECTION INPUT ;
    USE SIGNAL ;
    PORT
      LAYER Metal3 ;
        RECT  2274.6 611.74 2275 612.14 ;
    END
  END exec_req_i.wdata[60]
  PIN exec_req_i.wdata[61]
    DIRECTION INPUT ;
    USE SIGNAL ;
    PORT
      LAYER Metal3 ;
        RECT  2274.6 612.58 2275 612.98 ;
    END
  END exec_req_i.wdata[61]
  PIN exec_req_i.wdata[62]
    DIRECTION INPUT ;
    USE SIGNAL ;
    PORT
      LAYER Metal3 ;
        RECT  2274.6 613.42 2275 613.82 ;
    END
  END exec_req_i.wdata[62]
  PIN exec_req_i.wdata[63]
    DIRECTION INPUT ;
    USE SIGNAL ;
    PORT
      LAYER Metal3 ;
        RECT  2274.6 614.26 2275 614.66 ;
    END
  END exec_req_i.wdata[63]
  PIN exec_req_i.wdata[6]
    DIRECTION INPUT ;
    USE SIGNAL ;
    PORT
      LAYER Metal3 ;
        RECT  2274.6 545.38 2275 545.78 ;
    END
  END exec_req_i.wdata[6]
  PIN exec_req_i.wdata[7]
    DIRECTION INPUT ;
    USE SIGNAL ;
    PORT
      LAYER Metal3 ;
        RECT  2274.6 547.06 2275 547.46 ;
    END
  END exec_req_i.wdata[7]
  PIN exec_req_i.wdata[8]
    DIRECTION INPUT ;
    USE SIGNAL ;
    PORT
      LAYER Metal3 ;
        RECT  2274.6 548.74 2275 549.14 ;
    END
  END exec_req_i.wdata[8]
  PIN exec_req_i.wdata[9]
    DIRECTION INPUT ;
    USE SIGNAL ;
    PORT
      LAYER Metal3 ;
        RECT  2274.6 550.42 2275 550.82 ;
    END
  END exec_req_i.wdata[9]
  PIN exec_req_i.write
    DIRECTION INPUT ;
    USE SIGNAL ;
    PORT
      LAYER Metal3 ;
        RECT  2274.6 531.94 2275 532.34 ;
    END
  END exec_req_i.write
  PIN exec_rsp_o.fault
    DIRECTION OUTPUT ;
    USE SIGNAL ;
    PORT
      LAYER Metal3 ;
        RECT  2274.6 615.94 2275 616.34 ;
    END
  END exec_rsp_o.fault
  PIN exec_rsp_o.rdata[0]
    DIRECTION OUTPUT ;
    USE SIGNAL ;
    PORT
      LAYER Metal3 ;
        RECT  2274.6 617.62 2275 618.02 ;
    END
  END exec_rsp_o.rdata[0]
  PIN exec_rsp_o.rdata[10]
    DIRECTION OUTPUT ;
    USE SIGNAL ;
    PORT
      LAYER Metal3 ;
        RECT  2274.6 626.02 2275 626.42 ;
    END
  END exec_rsp_o.rdata[10]
  PIN exec_rsp_o.rdata[11]
    DIRECTION OUTPUT ;
    USE SIGNAL ;
    PORT
      LAYER Metal3 ;
        RECT  2274.6 626.86 2275 627.26 ;
    END
  END exec_rsp_o.rdata[11]
  PIN exec_rsp_o.rdata[12]
    DIRECTION OUTPUT ;
    USE SIGNAL ;
    PORT
      LAYER Metal3 ;
        RECT  2274.6 627.7 2275 628.1 ;
    END
  END exec_rsp_o.rdata[12]
  PIN exec_rsp_o.rdata[13]
    DIRECTION OUTPUT ;
    USE SIGNAL ;
    PORT
      LAYER Metal3 ;
        RECT  2274.6 628.54 2275 628.94 ;
    END
  END exec_rsp_o.rdata[13]
  PIN exec_rsp_o.rdata[14]
    DIRECTION OUTPUT ;
    USE SIGNAL ;
    PORT
      LAYER Metal3 ;
        RECT  2274.6 629.38 2275 629.78 ;
    END
  END exec_rsp_o.rdata[14]
  PIN exec_rsp_o.rdata[15]
    DIRECTION OUTPUT ;
    USE SIGNAL ;
    PORT
      LAYER Metal3 ;
        RECT  2274.6 630.22 2275 630.62 ;
    END
  END exec_rsp_o.rdata[15]
  PIN exec_rsp_o.rdata[16]
    DIRECTION OUTPUT ;
    USE SIGNAL ;
    PORT
      LAYER Metal3 ;
        RECT  2274.6 631.06 2275 631.46 ;
    END
  END exec_rsp_o.rdata[16]
  PIN exec_rsp_o.rdata[17]
    DIRECTION OUTPUT ;
    USE SIGNAL ;
    PORT
      LAYER Metal3 ;
        RECT  2274.6 631.9 2275 632.3 ;
    END
  END exec_rsp_o.rdata[17]
  PIN exec_rsp_o.rdata[18]
    DIRECTION OUTPUT ;
    USE SIGNAL ;
    PORT
      LAYER Metal3 ;
        RECT  2274.6 632.74 2275 633.14 ;
    END
  END exec_rsp_o.rdata[18]
  PIN exec_rsp_o.rdata[19]
    DIRECTION OUTPUT ;
    USE SIGNAL ;
    PORT
      LAYER Metal3 ;
        RECT  2274.6 633.58 2275 633.98 ;
    END
  END exec_rsp_o.rdata[19]
  PIN exec_rsp_o.rdata[1]
    DIRECTION OUTPUT ;
    USE SIGNAL ;
    PORT
      LAYER Metal3 ;
        RECT  2274.6 618.46 2275 618.86 ;
    END
  END exec_rsp_o.rdata[1]
  PIN exec_rsp_o.rdata[20]
    DIRECTION OUTPUT ;
    USE SIGNAL ;
    PORT
      LAYER Metal3 ;
        RECT  2274.6 634.42 2275 634.82 ;
    END
  END exec_rsp_o.rdata[20]
  PIN exec_rsp_o.rdata[21]
    DIRECTION OUTPUT ;
    USE SIGNAL ;
    PORT
      LAYER Metal3 ;
        RECT  2274.6 635.26 2275 635.66 ;
    END
  END exec_rsp_o.rdata[21]
  PIN exec_rsp_o.rdata[22]
    DIRECTION OUTPUT ;
    USE SIGNAL ;
    PORT
      LAYER Metal3 ;
        RECT  2274.6 636.1 2275 636.5 ;
    END
  END exec_rsp_o.rdata[22]
  PIN exec_rsp_o.rdata[23]
    DIRECTION OUTPUT ;
    USE SIGNAL ;
    PORT
      LAYER Metal3 ;
        RECT  2274.6 636.94 2275 637.34 ;
    END
  END exec_rsp_o.rdata[23]
  PIN exec_rsp_o.rdata[24]
    DIRECTION OUTPUT ;
    USE SIGNAL ;
    PORT
      LAYER Metal3 ;
        RECT  2274.6 637.78 2275 638.18 ;
    END
  END exec_rsp_o.rdata[24]
  PIN exec_rsp_o.rdata[25]
    DIRECTION OUTPUT ;
    USE SIGNAL ;
    PORT
      LAYER Metal3 ;
        RECT  2274.6 638.62 2275 639.02 ;
    END
  END exec_rsp_o.rdata[25]
  PIN exec_rsp_o.rdata[26]
    DIRECTION OUTPUT ;
    USE SIGNAL ;
    PORT
      LAYER Metal3 ;
        RECT  2274.6 639.46 2275 639.86 ;
    END
  END exec_rsp_o.rdata[26]
  PIN exec_rsp_o.rdata[27]
    DIRECTION OUTPUT ;
    USE SIGNAL ;
    PORT
      LAYER Metal3 ;
        RECT  2274.6 640.3 2275 640.7 ;
    END
  END exec_rsp_o.rdata[27]
  PIN exec_rsp_o.rdata[28]
    DIRECTION OUTPUT ;
    USE SIGNAL ;
    PORT
      LAYER Metal3 ;
        RECT  2274.6 641.14 2275 641.54 ;
    END
  END exec_rsp_o.rdata[28]
  PIN exec_rsp_o.rdata[29]
    DIRECTION OUTPUT ;
    USE SIGNAL ;
    PORT
      LAYER Metal3 ;
        RECT  2274.6 641.98 2275 642.38 ;
    END
  END exec_rsp_o.rdata[29]
  PIN exec_rsp_o.rdata[2]
    DIRECTION OUTPUT ;
    USE SIGNAL ;
    PORT
      LAYER Metal3 ;
        RECT  2274.6 619.3 2275 619.7 ;
    END
  END exec_rsp_o.rdata[2]
  PIN exec_rsp_o.rdata[30]
    DIRECTION OUTPUT ;
    USE SIGNAL ;
    PORT
      LAYER Metal3 ;
        RECT  2274.6 642.82 2275 643.22 ;
    END
  END exec_rsp_o.rdata[30]
  PIN exec_rsp_o.rdata[31]
    DIRECTION OUTPUT ;
    USE SIGNAL ;
    PORT
      LAYER Metal3 ;
        RECT  2274.6 643.66 2275 644.06 ;
    END
  END exec_rsp_o.rdata[31]
  PIN exec_rsp_o.rdata[32]
    DIRECTION OUTPUT ;
    USE SIGNAL ;
    PORT
      LAYER Metal3 ;
        RECT  2274.6 644.5 2275 644.9 ;
    END
  END exec_rsp_o.rdata[32]
  PIN exec_rsp_o.rdata[33]
    DIRECTION OUTPUT ;
    USE SIGNAL ;
    PORT
      LAYER Metal3 ;
        RECT  2274.6 645.34 2275 645.74 ;
    END
  END exec_rsp_o.rdata[33]
  PIN exec_rsp_o.rdata[34]
    DIRECTION OUTPUT ;
    USE SIGNAL ;
    PORT
      LAYER Metal3 ;
        RECT  2274.6 646.18 2275 646.58 ;
    END
  END exec_rsp_o.rdata[34]
  PIN exec_rsp_o.rdata[35]
    DIRECTION OUTPUT ;
    USE SIGNAL ;
    PORT
      LAYER Metal3 ;
        RECT  2274.6 647.02 2275 647.42 ;
    END
  END exec_rsp_o.rdata[35]
  PIN exec_rsp_o.rdata[36]
    DIRECTION OUTPUT ;
    USE SIGNAL ;
    PORT
      LAYER Metal3 ;
        RECT  2274.6 647.86 2275 648.26 ;
    END
  END exec_rsp_o.rdata[36]
  PIN exec_rsp_o.rdata[37]
    DIRECTION OUTPUT ;
    USE SIGNAL ;
    PORT
      LAYER Metal3 ;
        RECT  2274.6 648.7 2275 649.1 ;
    END
  END exec_rsp_o.rdata[37]
  PIN exec_rsp_o.rdata[38]
    DIRECTION OUTPUT ;
    USE SIGNAL ;
    PORT
      LAYER Metal3 ;
        RECT  2274.6 649.54 2275 649.94 ;
    END
  END exec_rsp_o.rdata[38]
  PIN exec_rsp_o.rdata[39]
    DIRECTION OUTPUT ;
    USE SIGNAL ;
    PORT
      LAYER Metal3 ;
        RECT  2274.6 650.38 2275 650.78 ;
    END
  END exec_rsp_o.rdata[39]
  PIN exec_rsp_o.rdata[3]
    DIRECTION OUTPUT ;
    USE SIGNAL ;
    PORT
      LAYER Metal3 ;
        RECT  2274.6 620.14 2275 620.54 ;
    END
  END exec_rsp_o.rdata[3]
  PIN exec_rsp_o.rdata[40]
    DIRECTION OUTPUT ;
    USE SIGNAL ;
    PORT
      LAYER Metal3 ;
        RECT  2274.6 651.22 2275 651.62 ;
    END
  END exec_rsp_o.rdata[40]
  PIN exec_rsp_o.rdata[41]
    DIRECTION OUTPUT ;
    USE SIGNAL ;
    PORT
      LAYER Metal3 ;
        RECT  2274.6 652.06 2275 652.46 ;
    END
  END exec_rsp_o.rdata[41]
  PIN exec_rsp_o.rdata[42]
    DIRECTION OUTPUT ;
    USE SIGNAL ;
    PORT
      LAYER Metal3 ;
        RECT  2274.6 652.9 2275 653.3 ;
    END
  END exec_rsp_o.rdata[42]
  PIN exec_rsp_o.rdata[43]
    DIRECTION OUTPUT ;
    USE SIGNAL ;
    PORT
      LAYER Metal3 ;
        RECT  2274.6 653.74 2275 654.14 ;
    END
  END exec_rsp_o.rdata[43]
  PIN exec_rsp_o.rdata[44]
    DIRECTION OUTPUT ;
    USE SIGNAL ;
    PORT
      LAYER Metal3 ;
        RECT  2274.6 654.58 2275 654.98 ;
    END
  END exec_rsp_o.rdata[44]
  PIN exec_rsp_o.rdata[45]
    DIRECTION OUTPUT ;
    USE SIGNAL ;
    PORT
      LAYER Metal3 ;
        RECT  2274.6 655.42 2275 655.82 ;
    END
  END exec_rsp_o.rdata[45]
  PIN exec_rsp_o.rdata[46]
    DIRECTION OUTPUT ;
    USE SIGNAL ;
    PORT
      LAYER Metal3 ;
        RECT  2274.6 656.26 2275 656.66 ;
    END
  END exec_rsp_o.rdata[46]
  PIN exec_rsp_o.rdata[47]
    DIRECTION OUTPUT ;
    USE SIGNAL ;
    PORT
      LAYER Metal3 ;
        RECT  2274.6 657.1 2275 657.5 ;
    END
  END exec_rsp_o.rdata[47]
  PIN exec_rsp_o.rdata[48]
    DIRECTION OUTPUT ;
    USE SIGNAL ;
    PORT
      LAYER Metal3 ;
        RECT  2274.6 657.94 2275 658.34 ;
    END
  END exec_rsp_o.rdata[48]
  PIN exec_rsp_o.rdata[49]
    DIRECTION OUTPUT ;
    USE SIGNAL ;
    PORT
      LAYER Metal3 ;
        RECT  2274.6 658.78 2275 659.18 ;
    END
  END exec_rsp_o.rdata[49]
  PIN exec_rsp_o.rdata[4]
    DIRECTION OUTPUT ;
    USE SIGNAL ;
    PORT
      LAYER Metal3 ;
        RECT  2274.6 620.98 2275 621.38 ;
    END
  END exec_rsp_o.rdata[4]
  PIN exec_rsp_o.rdata[50]
    DIRECTION OUTPUT ;
    USE SIGNAL ;
    PORT
      LAYER Metal3 ;
        RECT  2274.6 659.62 2275 660.02 ;
    END
  END exec_rsp_o.rdata[50]
  PIN exec_rsp_o.rdata[51]
    DIRECTION OUTPUT ;
    USE SIGNAL ;
    PORT
      LAYER Metal3 ;
        RECT  2274.6 660.46 2275 660.86 ;
    END
  END exec_rsp_o.rdata[51]
  PIN exec_rsp_o.rdata[52]
    DIRECTION OUTPUT ;
    USE SIGNAL ;
    PORT
      LAYER Metal3 ;
        RECT  2274.6 661.3 2275 661.7 ;
    END
  END exec_rsp_o.rdata[52]
  PIN exec_rsp_o.rdata[53]
    DIRECTION OUTPUT ;
    USE SIGNAL ;
    PORT
      LAYER Metal3 ;
        RECT  2274.6 662.14 2275 662.54 ;
    END
  END exec_rsp_o.rdata[53]
  PIN exec_rsp_o.rdata[54]
    DIRECTION OUTPUT ;
    USE SIGNAL ;
    PORT
      LAYER Metal3 ;
        RECT  2274.6 662.98 2275 663.38 ;
    END
  END exec_rsp_o.rdata[54]
  PIN exec_rsp_o.rdata[55]
    DIRECTION OUTPUT ;
    USE SIGNAL ;
    PORT
      LAYER Metal3 ;
        RECT  2274.6 663.82 2275 664.22 ;
    END
  END exec_rsp_o.rdata[55]
  PIN exec_rsp_o.rdata[56]
    DIRECTION OUTPUT ;
    USE SIGNAL ;
    PORT
      LAYER Metal3 ;
        RECT  2274.6 664.66 2275 665.06 ;
    END
  END exec_rsp_o.rdata[56]
  PIN exec_rsp_o.rdata[57]
    DIRECTION OUTPUT ;
    USE SIGNAL ;
    PORT
      LAYER Metal3 ;
        RECT  2274.6 665.5 2275 665.9 ;
    END
  END exec_rsp_o.rdata[57]
  PIN exec_rsp_o.rdata[58]
    DIRECTION OUTPUT ;
    USE SIGNAL ;
    PORT
      LAYER Metal3 ;
        RECT  2274.6 666.34 2275 666.74 ;
    END
  END exec_rsp_o.rdata[58]
  PIN exec_rsp_o.rdata[59]
    DIRECTION OUTPUT ;
    USE SIGNAL ;
    PORT
      LAYER Metal3 ;
        RECT  2274.6 667.18 2275 667.58 ;
    END
  END exec_rsp_o.rdata[59]
  PIN exec_rsp_o.rdata[5]
    DIRECTION OUTPUT ;
    USE SIGNAL ;
    PORT
      LAYER Metal3 ;
        RECT  2274.6 621.82 2275 622.22 ;
    END
  END exec_rsp_o.rdata[5]
  PIN exec_rsp_o.rdata[60]
    DIRECTION OUTPUT ;
    USE SIGNAL ;
    PORT
      LAYER Metal3 ;
        RECT  2274.6 668.02 2275 668.42 ;
    END
  END exec_rsp_o.rdata[60]
  PIN exec_rsp_o.rdata[61]
    DIRECTION OUTPUT ;
    USE SIGNAL ;
    PORT
      LAYER Metal3 ;
        RECT  2274.6 668.86 2275 669.26 ;
    END
  END exec_rsp_o.rdata[61]
  PIN exec_rsp_o.rdata[62]
    DIRECTION OUTPUT ;
    USE SIGNAL ;
    PORT
      LAYER Metal3 ;
        RECT  2274.6 669.7 2275 670.1 ;
    END
  END exec_rsp_o.rdata[62]
  PIN exec_rsp_o.rdata[63]
    DIRECTION OUTPUT ;
    USE SIGNAL ;
    PORT
      LAYER Metal3 ;
        RECT  2274.6 670.54 2275 670.94 ;
    END
  END exec_rsp_o.rdata[63]
  PIN exec_rsp_o.rdata[6]
    DIRECTION OUTPUT ;
    USE SIGNAL ;
    PORT
      LAYER Metal3 ;
        RECT  2274.6 622.66 2275 623.06 ;
    END
  END exec_rsp_o.rdata[6]
  PIN exec_rsp_o.rdata[7]
    DIRECTION OUTPUT ;
    USE SIGNAL ;
    PORT
      LAYER Metal3 ;
        RECT  2274.6 623.5 2275 623.9 ;
    END
  END exec_rsp_o.rdata[7]
  PIN exec_rsp_o.rdata[8]
    DIRECTION OUTPUT ;
    USE SIGNAL ;
    PORT
      LAYER Metal3 ;
        RECT  2274.6 624.34 2275 624.74 ;
    END
  END exec_rsp_o.rdata[8]
  PIN exec_rsp_o.rdata[9]
    DIRECTION OUTPUT ;
    USE SIGNAL ;
    PORT
      LAYER Metal3 ;
        RECT  2274.6 625.18 2275 625.58 ;
    END
  END exec_rsp_o.rdata[9]
  PIN exec_rsp_o.valid
    DIRECTION OUTPUT ;
    USE SIGNAL ;
    PORT
      LAYER Metal3 ;
        RECT  2274.6 616.78 2275 617.18 ;
    END
  END exec_rsp_o.valid
  PIN reset_i
    DIRECTION INPUT ;
    USE SIGNAL ;
    PORT
      LAYER Metal3 ;
        RECT  2274.6 386.62 2275 387.02 ;
    END
  END reset_i
  PIN stack_ready_o
    DIRECTION OUTPUT ;
    USE SIGNAL ;
    PORT
      LAYER Metal3 ;
        RECT  2274.6 473.14 2275 473.54 ;
    END
  END stack_ready_o
  PIN stack_req_i.address[0]
    DIRECTION INPUT ;
    USE SIGNAL ;
    PORT
      LAYER Metal3 ;
        RECT  2274.6 390.82 2275 391.22 ;
    END
  END stack_req_i.address[0]
  PIN stack_req_i.address[10]
    DIRECTION INPUT ;
    USE SIGNAL ;
    PORT
      LAYER Metal3 ;
        RECT  2274.6 409.3 2275 409.7 ;
    END
  END stack_req_i.address[10]
  PIN stack_req_i.address[11]
    DIRECTION INPUT ;
    USE SIGNAL ;
    PORT
      LAYER Metal3 ;
        RECT  2274.6 410.98 2275 411.38 ;
    END
  END stack_req_i.address[11]
  PIN stack_req_i.address[12]
    DIRECTION INPUT ;
    USE SIGNAL ;
    PORT
      LAYER Metal3 ;
        RECT  2274.6 412.66 2275 413.06 ;
    END
  END stack_req_i.address[12]
  PIN stack_req_i.address[13]
    DIRECTION INPUT ;
    USE SIGNAL ;
    PORT
      LAYER Metal3 ;
        RECT  2274.6 414.34 2275 414.74 ;
    END
  END stack_req_i.address[13]
  PIN stack_req_i.address[14]
    DIRECTION INPUT ;
    USE SIGNAL ;
    PORT
      LAYER Metal3 ;
        RECT  2274.6 416.02 2275 416.42 ;
    END
  END stack_req_i.address[14]
  PIN stack_req_i.address[15]
    DIRECTION INPUT ;
    USE SIGNAL ;
    PORT
      LAYER Metal3 ;
        RECT  2274.6 417.7 2275 418.1 ;
    END
  END stack_req_i.address[15]
  PIN stack_req_i.address[16]
    DIRECTION INPUT ;
    USE SIGNAL ;
    PORT
      LAYER Metal3 ;
        RECT  2274.6 419.38 2275 419.78 ;
    END
  END stack_req_i.address[16]
  PIN stack_req_i.address[17]
    DIRECTION INPUT ;
    USE SIGNAL ;
    PORT
      LAYER Metal3 ;
        RECT  2274.6 421.06 2275 421.46 ;
    END
  END stack_req_i.address[17]
  PIN stack_req_i.address[18]
    DIRECTION INPUT ;
    USE SIGNAL ;
    PORT
      LAYER Metal3 ;
        RECT  2274.6 422.74 2275 423.14 ;
    END
  END stack_req_i.address[18]
  PIN stack_req_i.address[19]
    DIRECTION INPUT ;
    USE SIGNAL ;
    PORT
      LAYER Metal3 ;
        RECT  2274.6 424.42 2275 424.82 ;
    END
  END stack_req_i.address[19]
  PIN stack_req_i.address[1]
    DIRECTION INPUT ;
    USE SIGNAL ;
    PORT
      LAYER Metal3 ;
        RECT  2274.6 393.34 2275 393.74 ;
    END
  END stack_req_i.address[1]
  PIN stack_req_i.address[20]
    DIRECTION INPUT ;
    USE SIGNAL ;
    PORT
      LAYER Metal3 ;
        RECT  2274.6 426.1 2275 426.5 ;
    END
  END stack_req_i.address[20]
  PIN stack_req_i.address[21]
    DIRECTION INPUT ;
    USE SIGNAL ;
    PORT
      LAYER Metal3 ;
        RECT  2274.6 427.78 2275 428.18 ;
    END
  END stack_req_i.address[21]
  PIN stack_req_i.address[22]
    DIRECTION INPUT ;
    USE SIGNAL ;
    PORT
      LAYER Metal3 ;
        RECT  2274.6 429.46 2275 429.86 ;
    END
  END stack_req_i.address[22]
  PIN stack_req_i.address[23]
    DIRECTION INPUT ;
    USE SIGNAL ;
    PORT
      LAYER Metal3 ;
        RECT  2274.6 431.14 2275 431.54 ;
    END
  END stack_req_i.address[23]
  PIN stack_req_i.address[24]
    DIRECTION INPUT ;
    USE SIGNAL ;
    PORT
      LAYER Metal3 ;
        RECT  2274.6 432.82 2275 433.22 ;
    END
  END stack_req_i.address[24]
  PIN stack_req_i.address[25]
    DIRECTION INPUT ;
    USE SIGNAL ;
    PORT
      LAYER Metal3 ;
        RECT  2274.6 434.5 2275 434.9 ;
    END
  END stack_req_i.address[25]
  PIN stack_req_i.address[26]
    DIRECTION INPUT ;
    USE SIGNAL ;
    PORT
      LAYER Metal3 ;
        RECT  2274.6 436.18 2275 436.58 ;
    END
  END stack_req_i.address[26]
  PIN stack_req_i.address[27]
    DIRECTION INPUT ;
    USE SIGNAL ;
    PORT
      LAYER Metal3 ;
        RECT  2274.6 437.86 2275 438.26 ;
    END
  END stack_req_i.address[27]
  PIN stack_req_i.address[28]
    DIRECTION INPUT ;
    USE SIGNAL ;
    PORT
      LAYER Metal3 ;
        RECT  2274.6 439.54 2275 439.94 ;
    END
  END stack_req_i.address[28]
  PIN stack_req_i.address[29]
    DIRECTION INPUT ;
    USE SIGNAL ;
    PORT
      LAYER Metal3 ;
        RECT  2274.6 441.22 2275 441.62 ;
    END
  END stack_req_i.address[29]
  PIN stack_req_i.address[2]
    DIRECTION INPUT ;
    USE SIGNAL ;
    PORT
      LAYER Metal3 ;
        RECT  2274.6 395.86 2275 396.26 ;
    END
  END stack_req_i.address[2]
  PIN stack_req_i.address[30]
    DIRECTION INPUT ;
    USE SIGNAL ;
    PORT
      LAYER Metal3 ;
        RECT  2274.6 442.9 2275 443.3 ;
    END
  END stack_req_i.address[30]
  PIN stack_req_i.address[31]
    DIRECTION INPUT ;
    USE SIGNAL ;
    PORT
      LAYER Metal3 ;
        RECT  2274.6 444.58 2275 444.98 ;
    END
  END stack_req_i.address[31]
  PIN stack_req_i.address[3]
    DIRECTION INPUT ;
    USE SIGNAL ;
    PORT
      LAYER Metal3 ;
        RECT  2274.6 397.54 2275 397.94 ;
    END
  END stack_req_i.address[3]
  PIN stack_req_i.address[4]
    DIRECTION INPUT ;
    USE SIGNAL ;
    PORT
      LAYER Metal3 ;
        RECT  2274.6 399.22 2275 399.62 ;
    END
  END stack_req_i.address[4]
  PIN stack_req_i.address[5]
    DIRECTION INPUT ;
    USE SIGNAL ;
    PORT
      LAYER Metal3 ;
        RECT  2274.6 400.9 2275 401.3 ;
    END
  END stack_req_i.address[5]
  PIN stack_req_i.address[6]
    DIRECTION INPUT ;
    USE SIGNAL ;
    PORT
      LAYER Metal3 ;
        RECT  2274.6 402.58 2275 402.98 ;
    END
  END stack_req_i.address[6]
  PIN stack_req_i.address[7]
    DIRECTION INPUT ;
    USE SIGNAL ;
    PORT
      LAYER Metal3 ;
        RECT  2274.6 404.26 2275 404.66 ;
    END
  END stack_req_i.address[7]
  PIN stack_req_i.address[8]
    DIRECTION INPUT ;
    USE SIGNAL ;
    PORT
      LAYER Metal3 ;
        RECT  2274.6 405.94 2275 406.34 ;
    END
  END stack_req_i.address[8]
  PIN stack_req_i.address[9]
    DIRECTION INPUT ;
    USE SIGNAL ;
    PORT
      LAYER Metal3 ;
        RECT  2274.6 407.62 2275 408.02 ;
    END
  END stack_req_i.address[9]
  PIN stack_req_i.probe
    DIRECTION INPUT ;
    USE SIGNAL ;
    PORT
      LAYER Metal3 ;
        RECT  2274.6 388.3 2275 388.7 ;
    END
  END stack_req_i.probe
  PIN stack_req_i.size[0]
    DIRECTION INPUT ;
    USE SIGNAL ;
    PORT
      LAYER Metal3 ;
        RECT  2274.6 391.66 2275 392.06 ;
    END
  END stack_req_i.size[0]
  PIN stack_req_i.size[1]
    DIRECTION INPUT ;
    USE SIGNAL ;
    PORT
      LAYER Metal3 ;
        RECT  2274.6 394.18 2275 394.58 ;
    END
  END stack_req_i.size[1]
  PIN stack_req_i.valid
    DIRECTION INPUT ;
    USE SIGNAL ;
    PORT
      LAYER Metal3 ;
        RECT  2274.6 389.14 2275 389.54 ;
    END
  END stack_req_i.valid
  PIN stack_req_i.wdata[0]
    DIRECTION INPUT ;
    USE SIGNAL ;
    PORT
      LAYER Metal3 ;
        RECT  2274.6 392.5 2275 392.9 ;
    END
  END stack_req_i.wdata[0]
  PIN stack_req_i.wdata[10]
    DIRECTION INPUT ;
    USE SIGNAL ;
    PORT
      LAYER Metal3 ;
        RECT  2274.6 410.14 2275 410.54 ;
    END
  END stack_req_i.wdata[10]
  PIN stack_req_i.wdata[11]
    DIRECTION INPUT ;
    USE SIGNAL ;
    PORT
      LAYER Metal3 ;
        RECT  2274.6 411.82 2275 412.22 ;
    END
  END stack_req_i.wdata[11]
  PIN stack_req_i.wdata[12]
    DIRECTION INPUT ;
    USE SIGNAL ;
    PORT
      LAYER Metal3 ;
        RECT  2274.6 413.5 2275 413.9 ;
    END
  END stack_req_i.wdata[12]
  PIN stack_req_i.wdata[13]
    DIRECTION INPUT ;
    USE SIGNAL ;
    PORT
      LAYER Metal3 ;
        RECT  2274.6 415.18 2275 415.58 ;
    END
  END stack_req_i.wdata[13]
  PIN stack_req_i.wdata[14]
    DIRECTION INPUT ;
    USE SIGNAL ;
    PORT
      LAYER Metal3 ;
        RECT  2274.6 416.86 2275 417.26 ;
    END
  END stack_req_i.wdata[14]
  PIN stack_req_i.wdata[15]
    DIRECTION INPUT ;
    USE SIGNAL ;
    PORT
      LAYER Metal3 ;
        RECT  2274.6 418.54 2275 418.94 ;
    END
  END stack_req_i.wdata[15]
  PIN stack_req_i.wdata[16]
    DIRECTION INPUT ;
    USE SIGNAL ;
    PORT
      LAYER Metal3 ;
        RECT  2274.6 420.22 2275 420.62 ;
    END
  END stack_req_i.wdata[16]
  PIN stack_req_i.wdata[17]
    DIRECTION INPUT ;
    USE SIGNAL ;
    PORT
      LAYER Metal3 ;
        RECT  2274.6 421.9 2275 422.3 ;
    END
  END stack_req_i.wdata[17]
  PIN stack_req_i.wdata[18]
    DIRECTION INPUT ;
    USE SIGNAL ;
    PORT
      LAYER Metal3 ;
        RECT  2274.6 423.58 2275 423.98 ;
    END
  END stack_req_i.wdata[18]
  PIN stack_req_i.wdata[19]
    DIRECTION INPUT ;
    USE SIGNAL ;
    PORT
      LAYER Metal3 ;
        RECT  2274.6 425.26 2275 425.66 ;
    END
  END stack_req_i.wdata[19]
  PIN stack_req_i.wdata[1]
    DIRECTION INPUT ;
    USE SIGNAL ;
    PORT
      LAYER Metal3 ;
        RECT  2274.6 395.02 2275 395.42 ;
    END
  END stack_req_i.wdata[1]
  PIN stack_req_i.wdata[20]
    DIRECTION INPUT ;
    USE SIGNAL ;
    PORT
      LAYER Metal3 ;
        RECT  2274.6 426.94 2275 427.34 ;
    END
  END stack_req_i.wdata[20]
  PIN stack_req_i.wdata[21]
    DIRECTION INPUT ;
    USE SIGNAL ;
    PORT
      LAYER Metal3 ;
        RECT  2274.6 428.62 2275 429.02 ;
    END
  END stack_req_i.wdata[21]
  PIN stack_req_i.wdata[22]
    DIRECTION INPUT ;
    USE SIGNAL ;
    PORT
      LAYER Metal3 ;
        RECT  2274.6 430.3 2275 430.7 ;
    END
  END stack_req_i.wdata[22]
  PIN stack_req_i.wdata[23]
    DIRECTION INPUT ;
    USE SIGNAL ;
    PORT
      LAYER Metal3 ;
        RECT  2274.6 431.98 2275 432.38 ;
    END
  END stack_req_i.wdata[23]
  PIN stack_req_i.wdata[24]
    DIRECTION INPUT ;
    USE SIGNAL ;
    PORT
      LAYER Metal3 ;
        RECT  2274.6 433.66 2275 434.06 ;
    END
  END stack_req_i.wdata[24]
  PIN stack_req_i.wdata[25]
    DIRECTION INPUT ;
    USE SIGNAL ;
    PORT
      LAYER Metal3 ;
        RECT  2274.6 435.34 2275 435.74 ;
    END
  END stack_req_i.wdata[25]
  PIN stack_req_i.wdata[26]
    DIRECTION INPUT ;
    USE SIGNAL ;
    PORT
      LAYER Metal3 ;
        RECT  2274.6 437.02 2275 437.42 ;
    END
  END stack_req_i.wdata[26]
  PIN stack_req_i.wdata[27]
    DIRECTION INPUT ;
    USE SIGNAL ;
    PORT
      LAYER Metal3 ;
        RECT  2274.6 438.7 2275 439.1 ;
    END
  END stack_req_i.wdata[27]
  PIN stack_req_i.wdata[28]
    DIRECTION INPUT ;
    USE SIGNAL ;
    PORT
      LAYER Metal3 ;
        RECT  2274.6 440.38 2275 440.78 ;
    END
  END stack_req_i.wdata[28]
  PIN stack_req_i.wdata[29]
    DIRECTION INPUT ;
    USE SIGNAL ;
    PORT
      LAYER Metal3 ;
        RECT  2274.6 442.06 2275 442.46 ;
    END
  END stack_req_i.wdata[29]
  PIN stack_req_i.wdata[2]
    DIRECTION INPUT ;
    USE SIGNAL ;
    PORT
      LAYER Metal3 ;
        RECT  2274.6 396.7 2275 397.1 ;
    END
  END stack_req_i.wdata[2]
  PIN stack_req_i.wdata[30]
    DIRECTION INPUT ;
    USE SIGNAL ;
    PORT
      LAYER Metal3 ;
        RECT  2274.6 443.74 2275 444.14 ;
    END
  END stack_req_i.wdata[30]
  PIN stack_req_i.wdata[31]
    DIRECTION INPUT ;
    USE SIGNAL ;
    PORT
      LAYER Metal3 ;
        RECT  2274.6 445.42 2275 445.82 ;
    END
  END stack_req_i.wdata[31]
  PIN stack_req_i.wdata[32]
    DIRECTION INPUT ;
    USE SIGNAL ;
    PORT
      LAYER Metal3 ;
        RECT  2274.6 446.26 2275 446.66 ;
    END
  END stack_req_i.wdata[32]
  PIN stack_req_i.wdata[33]
    DIRECTION INPUT ;
    USE SIGNAL ;
    PORT
      LAYER Metal3 ;
        RECT  2274.6 447.1 2275 447.5 ;
    END
  END stack_req_i.wdata[33]
  PIN stack_req_i.wdata[34]
    DIRECTION INPUT ;
    USE SIGNAL ;
    PORT
      LAYER Metal3 ;
        RECT  2274.6 447.94 2275 448.34 ;
    END
  END stack_req_i.wdata[34]
  PIN stack_req_i.wdata[35]
    DIRECTION INPUT ;
    USE SIGNAL ;
    PORT
      LAYER Metal3 ;
        RECT  2274.6 448.78 2275 449.18 ;
    END
  END stack_req_i.wdata[35]
  PIN stack_req_i.wdata[36]
    DIRECTION INPUT ;
    USE SIGNAL ;
    PORT
      LAYER Metal3 ;
        RECT  2274.6 449.62 2275 450.02 ;
    END
  END stack_req_i.wdata[36]
  PIN stack_req_i.wdata[37]
    DIRECTION INPUT ;
    USE SIGNAL ;
    PORT
      LAYER Metal3 ;
        RECT  2274.6 450.46 2275 450.86 ;
    END
  END stack_req_i.wdata[37]
  PIN stack_req_i.wdata[38]
    DIRECTION INPUT ;
    USE SIGNAL ;
    PORT
      LAYER Metal3 ;
        RECT  2274.6 451.3 2275 451.7 ;
    END
  END stack_req_i.wdata[38]
  PIN stack_req_i.wdata[39]
    DIRECTION INPUT ;
    USE SIGNAL ;
    PORT
      LAYER Metal3 ;
        RECT  2274.6 452.14 2275 452.54 ;
    END
  END stack_req_i.wdata[39]
  PIN stack_req_i.wdata[3]
    DIRECTION INPUT ;
    USE SIGNAL ;
    PORT
      LAYER Metal3 ;
        RECT  2274.6 398.38 2275 398.78 ;
    END
  END stack_req_i.wdata[3]
  PIN stack_req_i.wdata[40]
    DIRECTION INPUT ;
    USE SIGNAL ;
    PORT
      LAYER Metal3 ;
        RECT  2274.6 452.98 2275 453.38 ;
    END
  END stack_req_i.wdata[40]
  PIN stack_req_i.wdata[41]
    DIRECTION INPUT ;
    USE SIGNAL ;
    PORT
      LAYER Metal3 ;
        RECT  2274.6 453.82 2275 454.22 ;
    END
  END stack_req_i.wdata[41]
  PIN stack_req_i.wdata[42]
    DIRECTION INPUT ;
    USE SIGNAL ;
    PORT
      LAYER Metal3 ;
        RECT  2274.6 454.66 2275 455.06 ;
    END
  END stack_req_i.wdata[42]
  PIN stack_req_i.wdata[43]
    DIRECTION INPUT ;
    USE SIGNAL ;
    PORT
      LAYER Metal3 ;
        RECT  2274.6 455.5 2275 455.9 ;
    END
  END stack_req_i.wdata[43]
  PIN stack_req_i.wdata[44]
    DIRECTION INPUT ;
    USE SIGNAL ;
    PORT
      LAYER Metal3 ;
        RECT  2274.6 456.34 2275 456.74 ;
    END
  END stack_req_i.wdata[44]
  PIN stack_req_i.wdata[45]
    DIRECTION INPUT ;
    USE SIGNAL ;
    PORT
      LAYER Metal3 ;
        RECT  2274.6 457.18 2275 457.58 ;
    END
  END stack_req_i.wdata[45]
  PIN stack_req_i.wdata[46]
    DIRECTION INPUT ;
    USE SIGNAL ;
    PORT
      LAYER Metal3 ;
        RECT  2274.6 458.02 2275 458.42 ;
    END
  END stack_req_i.wdata[46]
  PIN stack_req_i.wdata[47]
    DIRECTION INPUT ;
    USE SIGNAL ;
    PORT
      LAYER Metal3 ;
        RECT  2274.6 458.86 2275 459.26 ;
    END
  END stack_req_i.wdata[47]
  PIN stack_req_i.wdata[48]
    DIRECTION INPUT ;
    USE SIGNAL ;
    PORT
      LAYER Metal3 ;
        RECT  2274.6 459.7 2275 460.1 ;
    END
  END stack_req_i.wdata[48]
  PIN stack_req_i.wdata[49]
    DIRECTION INPUT ;
    USE SIGNAL ;
    PORT
      LAYER Metal3 ;
        RECT  2274.6 460.54 2275 460.94 ;
    END
  END stack_req_i.wdata[49]
  PIN stack_req_i.wdata[4]
    DIRECTION INPUT ;
    USE SIGNAL ;
    PORT
      LAYER Metal3 ;
        RECT  2274.6 400.06 2275 400.46 ;
    END
  END stack_req_i.wdata[4]
  PIN stack_req_i.wdata[50]
    DIRECTION INPUT ;
    USE SIGNAL ;
    PORT
      LAYER Metal3 ;
        RECT  2274.6 461.38 2275 461.78 ;
    END
  END stack_req_i.wdata[50]
  PIN stack_req_i.wdata[51]
    DIRECTION INPUT ;
    USE SIGNAL ;
    PORT
      LAYER Metal3 ;
        RECT  2274.6 462.22 2275 462.62 ;
    END
  END stack_req_i.wdata[51]
  PIN stack_req_i.wdata[52]
    DIRECTION INPUT ;
    USE SIGNAL ;
    PORT
      LAYER Metal3 ;
        RECT  2274.6 463.06 2275 463.46 ;
    END
  END stack_req_i.wdata[52]
  PIN stack_req_i.wdata[53]
    DIRECTION INPUT ;
    USE SIGNAL ;
    PORT
      LAYER Metal3 ;
        RECT  2274.6 463.9 2275 464.3 ;
    END
  END stack_req_i.wdata[53]
  PIN stack_req_i.wdata[54]
    DIRECTION INPUT ;
    USE SIGNAL ;
    PORT
      LAYER Metal3 ;
        RECT  2274.6 464.74 2275 465.14 ;
    END
  END stack_req_i.wdata[54]
  PIN stack_req_i.wdata[55]
    DIRECTION INPUT ;
    USE SIGNAL ;
    PORT
      LAYER Metal3 ;
        RECT  2274.6 465.58 2275 465.98 ;
    END
  END stack_req_i.wdata[55]
  PIN stack_req_i.wdata[56]
    DIRECTION INPUT ;
    USE SIGNAL ;
    PORT
      LAYER Metal3 ;
        RECT  2274.6 466.42 2275 466.82 ;
    END
  END stack_req_i.wdata[56]
  PIN stack_req_i.wdata[57]
    DIRECTION INPUT ;
    USE SIGNAL ;
    PORT
      LAYER Metal3 ;
        RECT  2274.6 467.26 2275 467.66 ;
    END
  END stack_req_i.wdata[57]
  PIN stack_req_i.wdata[58]
    DIRECTION INPUT ;
    USE SIGNAL ;
    PORT
      LAYER Metal3 ;
        RECT  2274.6 468.1 2275 468.5 ;
    END
  END stack_req_i.wdata[58]
  PIN stack_req_i.wdata[59]
    DIRECTION INPUT ;
    USE SIGNAL ;
    PORT
      LAYER Metal3 ;
        RECT  2274.6 468.94 2275 469.34 ;
    END
  END stack_req_i.wdata[59]
  PIN stack_req_i.wdata[5]
    DIRECTION INPUT ;
    USE SIGNAL ;
    PORT
      LAYER Metal3 ;
        RECT  2274.6 401.74 2275 402.14 ;
    END
  END stack_req_i.wdata[5]
  PIN stack_req_i.wdata[60]
    DIRECTION INPUT ;
    USE SIGNAL ;
    PORT
      LAYER Metal3 ;
        RECT  2274.6 469.78 2275 470.18 ;
    END
  END stack_req_i.wdata[60]
  PIN stack_req_i.wdata[61]
    DIRECTION INPUT ;
    USE SIGNAL ;
    PORT
      LAYER Metal3 ;
        RECT  2274.6 470.62 2275 471.02 ;
    END
  END stack_req_i.wdata[61]
  PIN stack_req_i.wdata[62]
    DIRECTION INPUT ;
    USE SIGNAL ;
    PORT
      LAYER Metal3 ;
        RECT  2274.6 471.46 2275 471.86 ;
    END
  END stack_req_i.wdata[62]
  PIN stack_req_i.wdata[63]
    DIRECTION INPUT ;
    USE SIGNAL ;
    PORT
      LAYER Metal3 ;
        RECT  2274.6 472.3 2275 472.7 ;
    END
  END stack_req_i.wdata[63]
  PIN stack_req_i.wdata[6]
    DIRECTION INPUT ;
    USE SIGNAL ;
    PORT
      LAYER Metal3 ;
        RECT  2274.6 403.42 2275 403.82 ;
    END
  END stack_req_i.wdata[6]
  PIN stack_req_i.wdata[7]
    DIRECTION INPUT ;
    USE SIGNAL ;
    PORT
      LAYER Metal3 ;
        RECT  2274.6 405.1 2275 405.5 ;
    END
  END stack_req_i.wdata[7]
  PIN stack_req_i.wdata[8]
    DIRECTION INPUT ;
    USE SIGNAL ;
    PORT
      LAYER Metal3 ;
        RECT  2274.6 406.78 2275 407.18 ;
    END
  END stack_req_i.wdata[8]
  PIN stack_req_i.wdata[9]
    DIRECTION INPUT ;
    USE SIGNAL ;
    PORT
      LAYER Metal3 ;
        RECT  2274.6 408.46 2275 408.86 ;
    END
  END stack_req_i.wdata[9]
  PIN stack_req_i.write
    DIRECTION INPUT ;
    USE SIGNAL ;
    PORT
      LAYER Metal3 ;
        RECT  2274.6 389.98 2275 390.38 ;
    END
  END stack_req_i.write
  PIN stack_rsp_o.fault
    DIRECTION OUTPUT ;
    USE SIGNAL ;
    PORT
      LAYER Metal3 ;
        RECT  2274.6 473.98 2275 474.38 ;
    END
  END stack_rsp_o.fault
  PIN stack_rsp_o.rdata[0]
    DIRECTION OUTPUT ;
    USE SIGNAL ;
    PORT
      LAYER Metal3 ;
        RECT  2274.6 475.66 2275 476.06 ;
    END
  END stack_rsp_o.rdata[0]
  PIN stack_rsp_o.rdata[10]
    DIRECTION OUTPUT ;
    USE SIGNAL ;
    PORT
      LAYER Metal3 ;
        RECT  2274.6 484.06 2275 484.46 ;
    END
  END stack_rsp_o.rdata[10]
  PIN stack_rsp_o.rdata[11]
    DIRECTION OUTPUT ;
    USE SIGNAL ;
    PORT
      LAYER Metal3 ;
        RECT  2274.6 484.9 2275 485.3 ;
    END
  END stack_rsp_o.rdata[11]
  PIN stack_rsp_o.rdata[12]
    DIRECTION OUTPUT ;
    USE SIGNAL ;
    PORT
      LAYER Metal3 ;
        RECT  2274.6 485.74 2275 486.14 ;
    END
  END stack_rsp_o.rdata[12]
  PIN stack_rsp_o.rdata[13]
    DIRECTION OUTPUT ;
    USE SIGNAL ;
    PORT
      LAYER Metal3 ;
        RECT  2274.6 486.58 2275 486.98 ;
    END
  END stack_rsp_o.rdata[13]
  PIN stack_rsp_o.rdata[14]
    DIRECTION OUTPUT ;
    USE SIGNAL ;
    PORT
      LAYER Metal3 ;
        RECT  2274.6 487.42 2275 487.82 ;
    END
  END stack_rsp_o.rdata[14]
  PIN stack_rsp_o.rdata[15]
    DIRECTION OUTPUT ;
    USE SIGNAL ;
    PORT
      LAYER Metal3 ;
        RECT  2274.6 488.26 2275 488.66 ;
    END
  END stack_rsp_o.rdata[15]
  PIN stack_rsp_o.rdata[16]
    DIRECTION OUTPUT ;
    USE SIGNAL ;
    PORT
      LAYER Metal3 ;
        RECT  2274.6 489.1 2275 489.5 ;
    END
  END stack_rsp_o.rdata[16]
  PIN stack_rsp_o.rdata[17]
    DIRECTION OUTPUT ;
    USE SIGNAL ;
    PORT
      LAYER Metal3 ;
        RECT  2274.6 489.94 2275 490.34 ;
    END
  END stack_rsp_o.rdata[17]
  PIN stack_rsp_o.rdata[18]
    DIRECTION OUTPUT ;
    USE SIGNAL ;
    PORT
      LAYER Metal3 ;
        RECT  2274.6 490.78 2275 491.18 ;
    END
  END stack_rsp_o.rdata[18]
  PIN stack_rsp_o.rdata[19]
    DIRECTION OUTPUT ;
    USE SIGNAL ;
    PORT
      LAYER Metal3 ;
        RECT  2274.6 491.62 2275 492.02 ;
    END
  END stack_rsp_o.rdata[19]
  PIN stack_rsp_o.rdata[1]
    DIRECTION OUTPUT ;
    USE SIGNAL ;
    PORT
      LAYER Metal3 ;
        RECT  2274.6 476.5 2275 476.9 ;
    END
  END stack_rsp_o.rdata[1]
  PIN stack_rsp_o.rdata[20]
    DIRECTION OUTPUT ;
    USE SIGNAL ;
    PORT
      LAYER Metal3 ;
        RECT  2274.6 492.46 2275 492.86 ;
    END
  END stack_rsp_o.rdata[20]
  PIN stack_rsp_o.rdata[21]
    DIRECTION OUTPUT ;
    USE SIGNAL ;
    PORT
      LAYER Metal3 ;
        RECT  2274.6 493.3 2275 493.7 ;
    END
  END stack_rsp_o.rdata[21]
  PIN stack_rsp_o.rdata[22]
    DIRECTION OUTPUT ;
    USE SIGNAL ;
    PORT
      LAYER Metal3 ;
        RECT  2274.6 494.14 2275 494.54 ;
    END
  END stack_rsp_o.rdata[22]
  PIN stack_rsp_o.rdata[23]
    DIRECTION OUTPUT ;
    USE SIGNAL ;
    PORT
      LAYER Metal3 ;
        RECT  2274.6 494.98 2275 495.38 ;
    END
  END stack_rsp_o.rdata[23]
  PIN stack_rsp_o.rdata[24]
    DIRECTION OUTPUT ;
    USE SIGNAL ;
    PORT
      LAYER Metal3 ;
        RECT  2274.6 495.82 2275 496.22 ;
    END
  END stack_rsp_o.rdata[24]
  PIN stack_rsp_o.rdata[25]
    DIRECTION OUTPUT ;
    USE SIGNAL ;
    PORT
      LAYER Metal3 ;
        RECT  2274.6 496.66 2275 497.06 ;
    END
  END stack_rsp_o.rdata[25]
  PIN stack_rsp_o.rdata[26]
    DIRECTION OUTPUT ;
    USE SIGNAL ;
    PORT
      LAYER Metal3 ;
        RECT  2274.6 497.5 2275 497.9 ;
    END
  END stack_rsp_o.rdata[26]
  PIN stack_rsp_o.rdata[27]
    DIRECTION OUTPUT ;
    USE SIGNAL ;
    PORT
      LAYER Metal3 ;
        RECT  2274.6 498.34 2275 498.74 ;
    END
  END stack_rsp_o.rdata[27]
  PIN stack_rsp_o.rdata[28]
    DIRECTION OUTPUT ;
    USE SIGNAL ;
    PORT
      LAYER Metal3 ;
        RECT  2274.6 499.18 2275 499.58 ;
    END
  END stack_rsp_o.rdata[28]
  PIN stack_rsp_o.rdata[29]
    DIRECTION OUTPUT ;
    USE SIGNAL ;
    PORT
      LAYER Metal3 ;
        RECT  2274.6 500.02 2275 500.42 ;
    END
  END stack_rsp_o.rdata[29]
  PIN stack_rsp_o.rdata[2]
    DIRECTION OUTPUT ;
    USE SIGNAL ;
    PORT
      LAYER Metal3 ;
        RECT  2274.6 477.34 2275 477.74 ;
    END
  END stack_rsp_o.rdata[2]
  PIN stack_rsp_o.rdata[30]
    DIRECTION OUTPUT ;
    USE SIGNAL ;
    PORT
      LAYER Metal3 ;
        RECT  2274.6 500.86 2275 501.26 ;
    END
  END stack_rsp_o.rdata[30]
  PIN stack_rsp_o.rdata[31]
    DIRECTION OUTPUT ;
    USE SIGNAL ;
    PORT
      LAYER Metal3 ;
        RECT  2274.6 501.7 2275 502.1 ;
    END
  END stack_rsp_o.rdata[31]
  PIN stack_rsp_o.rdata[32]
    DIRECTION OUTPUT ;
    USE SIGNAL ;
    PORT
      LAYER Metal3 ;
        RECT  2274.6 502.54 2275 502.94 ;
    END
  END stack_rsp_o.rdata[32]
  PIN stack_rsp_o.rdata[33]
    DIRECTION OUTPUT ;
    USE SIGNAL ;
    PORT
      LAYER Metal3 ;
        RECT  2274.6 503.38 2275 503.78 ;
    END
  END stack_rsp_o.rdata[33]
  PIN stack_rsp_o.rdata[34]
    DIRECTION OUTPUT ;
    USE SIGNAL ;
    PORT
      LAYER Metal3 ;
        RECT  2274.6 504.22 2275 504.62 ;
    END
  END stack_rsp_o.rdata[34]
  PIN stack_rsp_o.rdata[35]
    DIRECTION OUTPUT ;
    USE SIGNAL ;
    PORT
      LAYER Metal3 ;
        RECT  2274.6 505.06 2275 505.46 ;
    END
  END stack_rsp_o.rdata[35]
  PIN stack_rsp_o.rdata[36]
    DIRECTION OUTPUT ;
    USE SIGNAL ;
    PORT
      LAYER Metal3 ;
        RECT  2274.6 505.9 2275 506.3 ;
    END
  END stack_rsp_o.rdata[36]
  PIN stack_rsp_o.rdata[37]
    DIRECTION OUTPUT ;
    USE SIGNAL ;
    PORT
      LAYER Metal3 ;
        RECT  2274.6 506.74 2275 507.14 ;
    END
  END stack_rsp_o.rdata[37]
  PIN stack_rsp_o.rdata[38]
    DIRECTION OUTPUT ;
    USE SIGNAL ;
    PORT
      LAYER Metal3 ;
        RECT  2274.6 507.58 2275 507.98 ;
    END
  END stack_rsp_o.rdata[38]
  PIN stack_rsp_o.rdata[39]
    DIRECTION OUTPUT ;
    USE SIGNAL ;
    PORT
      LAYER Metal3 ;
        RECT  2274.6 508.42 2275 508.82 ;
    END
  END stack_rsp_o.rdata[39]
  PIN stack_rsp_o.rdata[3]
    DIRECTION OUTPUT ;
    USE SIGNAL ;
    PORT
      LAYER Metal3 ;
        RECT  2274.6 478.18 2275 478.58 ;
    END
  END stack_rsp_o.rdata[3]
  PIN stack_rsp_o.rdata[40]
    DIRECTION OUTPUT ;
    USE SIGNAL ;
    PORT
      LAYER Metal3 ;
        RECT  2274.6 509.26 2275 509.66 ;
    END
  END stack_rsp_o.rdata[40]
  PIN stack_rsp_o.rdata[41]
    DIRECTION OUTPUT ;
    USE SIGNAL ;
    PORT
      LAYER Metal3 ;
        RECT  2274.6 510.1 2275 510.5 ;
    END
  END stack_rsp_o.rdata[41]
  PIN stack_rsp_o.rdata[42]
    DIRECTION OUTPUT ;
    USE SIGNAL ;
    PORT
      LAYER Metal3 ;
        RECT  2274.6 510.94 2275 511.34 ;
    END
  END stack_rsp_o.rdata[42]
  PIN stack_rsp_o.rdata[43]
    DIRECTION OUTPUT ;
    USE SIGNAL ;
    PORT
      LAYER Metal3 ;
        RECT  2274.6 511.78 2275 512.18 ;
    END
  END stack_rsp_o.rdata[43]
  PIN stack_rsp_o.rdata[44]
    DIRECTION OUTPUT ;
    USE SIGNAL ;
    PORT
      LAYER Metal3 ;
        RECT  2274.6 512.62 2275 513.02 ;
    END
  END stack_rsp_o.rdata[44]
  PIN stack_rsp_o.rdata[45]
    DIRECTION OUTPUT ;
    USE SIGNAL ;
    PORT
      LAYER Metal3 ;
        RECT  2274.6 513.46 2275 513.86 ;
    END
  END stack_rsp_o.rdata[45]
  PIN stack_rsp_o.rdata[46]
    DIRECTION OUTPUT ;
    USE SIGNAL ;
    PORT
      LAYER Metal3 ;
        RECT  2274.6 514.3 2275 514.7 ;
    END
  END stack_rsp_o.rdata[46]
  PIN stack_rsp_o.rdata[47]
    DIRECTION OUTPUT ;
    USE SIGNAL ;
    PORT
      LAYER Metal3 ;
        RECT  2274.6 515.14 2275 515.54 ;
    END
  END stack_rsp_o.rdata[47]
  PIN stack_rsp_o.rdata[48]
    DIRECTION OUTPUT ;
    USE SIGNAL ;
    PORT
      LAYER Metal3 ;
        RECT  2274.6 515.98 2275 516.38 ;
    END
  END stack_rsp_o.rdata[48]
  PIN stack_rsp_o.rdata[49]
    DIRECTION OUTPUT ;
    USE SIGNAL ;
    PORT
      LAYER Metal3 ;
        RECT  2274.6 516.82 2275 517.22 ;
    END
  END stack_rsp_o.rdata[49]
  PIN stack_rsp_o.rdata[4]
    DIRECTION OUTPUT ;
    USE SIGNAL ;
    PORT
      LAYER Metal3 ;
        RECT  2274.6 479.02 2275 479.42 ;
    END
  END stack_rsp_o.rdata[4]
  PIN stack_rsp_o.rdata[50]
    DIRECTION OUTPUT ;
    USE SIGNAL ;
    PORT
      LAYER Metal3 ;
        RECT  2274.6 517.66 2275 518.06 ;
    END
  END stack_rsp_o.rdata[50]
  PIN stack_rsp_o.rdata[51]
    DIRECTION OUTPUT ;
    USE SIGNAL ;
    PORT
      LAYER Metal3 ;
        RECT  2274.6 518.5 2275 518.9 ;
    END
  END stack_rsp_o.rdata[51]
  PIN stack_rsp_o.rdata[52]
    DIRECTION OUTPUT ;
    USE SIGNAL ;
    PORT
      LAYER Metal3 ;
        RECT  2274.6 519.34 2275 519.74 ;
    END
  END stack_rsp_o.rdata[52]
  PIN stack_rsp_o.rdata[53]
    DIRECTION OUTPUT ;
    USE SIGNAL ;
    PORT
      LAYER Metal3 ;
        RECT  2274.6 520.18 2275 520.58 ;
    END
  END stack_rsp_o.rdata[53]
  PIN stack_rsp_o.rdata[54]
    DIRECTION OUTPUT ;
    USE SIGNAL ;
    PORT
      LAYER Metal3 ;
        RECT  2274.6 521.02 2275 521.42 ;
    END
  END stack_rsp_o.rdata[54]
  PIN stack_rsp_o.rdata[55]
    DIRECTION OUTPUT ;
    USE SIGNAL ;
    PORT
      LAYER Metal3 ;
        RECT  2274.6 521.86 2275 522.26 ;
    END
  END stack_rsp_o.rdata[55]
  PIN stack_rsp_o.rdata[56]
    DIRECTION OUTPUT ;
    USE SIGNAL ;
    PORT
      LAYER Metal3 ;
        RECT  2274.6 522.7 2275 523.1 ;
    END
  END stack_rsp_o.rdata[56]
  PIN stack_rsp_o.rdata[57]
    DIRECTION OUTPUT ;
    USE SIGNAL ;
    PORT
      LAYER Metal3 ;
        RECT  2274.6 523.54 2275 523.94 ;
    END
  END stack_rsp_o.rdata[57]
  PIN stack_rsp_o.rdata[58]
    DIRECTION OUTPUT ;
    USE SIGNAL ;
    PORT
      LAYER Metal3 ;
        RECT  2274.6 524.38 2275 524.78 ;
    END
  END stack_rsp_o.rdata[58]
  PIN stack_rsp_o.rdata[59]
    DIRECTION OUTPUT ;
    USE SIGNAL ;
    PORT
      LAYER Metal3 ;
        RECT  2274.6 525.22 2275 525.62 ;
    END
  END stack_rsp_o.rdata[59]
  PIN stack_rsp_o.rdata[5]
    DIRECTION OUTPUT ;
    USE SIGNAL ;
    PORT
      LAYER Metal3 ;
        RECT  2274.6 479.86 2275 480.26 ;
    END
  END stack_rsp_o.rdata[5]
  PIN stack_rsp_o.rdata[60]
    DIRECTION OUTPUT ;
    USE SIGNAL ;
    PORT
      LAYER Metal3 ;
        RECT  2274.6 526.06 2275 526.46 ;
    END
  END stack_rsp_o.rdata[60]
  PIN stack_rsp_o.rdata[61]
    DIRECTION OUTPUT ;
    USE SIGNAL ;
    PORT
      LAYER Metal3 ;
        RECT  2274.6 526.9 2275 527.3 ;
    END
  END stack_rsp_o.rdata[61]
  PIN stack_rsp_o.rdata[62]
    DIRECTION OUTPUT ;
    USE SIGNAL ;
    PORT
      LAYER Metal3 ;
        RECT  2274.6 527.74 2275 528.14 ;
    END
  END stack_rsp_o.rdata[62]
  PIN stack_rsp_o.rdata[63]
    DIRECTION OUTPUT ;
    USE SIGNAL ;
    PORT
      LAYER Metal3 ;
        RECT  2274.6 528.58 2275 528.98 ;
    END
  END stack_rsp_o.rdata[63]
  PIN stack_rsp_o.rdata[6]
    DIRECTION OUTPUT ;
    USE SIGNAL ;
    PORT
      LAYER Metal3 ;
        RECT  2274.6 480.7 2275 481.1 ;
    END
  END stack_rsp_o.rdata[6]
  PIN stack_rsp_o.rdata[7]
    DIRECTION OUTPUT ;
    USE SIGNAL ;
    PORT
      LAYER Metal3 ;
        RECT  2274.6 481.54 2275 481.94 ;
    END
  END stack_rsp_o.rdata[7]
  PIN stack_rsp_o.rdata[8]
    DIRECTION OUTPUT ;
    USE SIGNAL ;
    PORT
      LAYER Metal3 ;
        RECT  2274.6 482.38 2275 482.78 ;
    END
  END stack_rsp_o.rdata[8]
  PIN stack_rsp_o.rdata[9]
    DIRECTION OUTPUT ;
    USE SIGNAL ;
    PORT
      LAYER Metal3 ;
        RECT  2274.6 483.22 2275 483.62 ;
    END
  END stack_rsp_o.rdata[9]
  PIN stack_rsp_o.valid
    DIRECTION OUTPUT ;
    USE SIGNAL ;
    PORT
      LAYER Metal3 ;
        RECT  2274.6 474.82 2275 475.22 ;
    END
  END stack_rsp_o.valid
  PIN VPWR
    DIRECTION INOUT ;
    USE POWER ;
    PORT
      LAYER TopMetal1 ;
        RECT  5.76 1024.12 2268.96 1026.12 ;
        RECT  5.76 974.12 2268.96 976.12 ;
        RECT  5.76 924.12 2268.96 926.12 ;
        RECT  5.76 874.12 2268.96 876.12 ;
        RECT  5.76 824.12 2268.96 826.12 ;
        RECT  5.76 774.12 2268.96 776.12 ;
        RECT  5.76 724.12 2268.96 726.12 ;
        RECT  5.76 674.12 2268.96 676.12 ;
        RECT  5.76 624.12 2268.96 626.12 ;
        RECT  5.76 574.12 2268.96 576.12 ;
        RECT  5.76 524.12 2268.96 526.12 ;
        RECT  5.76 474.12 2268.96 476.12 ;
        RECT  5.76 424.12 2268.96 426.12 ;
        RECT  5.76 374.12 2268.96 376.12 ;
        RECT  5.76 324.12 2268.96 326.12 ;
        RECT  5.76 274.12 2268.96 276.12 ;
        RECT  5.76 224.12 2268.96 226.12 ;
        RECT  5.76 174.12 2268.96 176.12 ;
        RECT  5.76 124.12 2268.96 126.12 ;
        RECT  5.76 74.12 2268.96 76.12 ;
        RECT  5.76 24.12 2268.96 26.12 ;
      LAYER Metal4 ;
        RECT  2265.26 14.9 2266.26 1043.5 ;
        RECT  2215.26 145.25 2216.26 908.83 ;
        RECT  2165.26 145.49 2166.26 908.59 ;
        RECT  2115.26 145.49 2116.26 908.59 ;
        RECT  2065.26 145.49 2066.26 908.59 ;
        RECT  2015.26 145.49 2016.26 908.59 ;
        RECT  1965.26 145.49 1966.26 908.59 ;
        RECT  1915.26 145.49 1916.26 908.59 ;
        RECT  1865.26 145.25 1866.26 908.83 ;
        RECT  1815.26 145.49 1816.26 908.59 ;
        RECT  1765.26 145.49 1766.26 908.59 ;
        RECT  1715.26 145.49 1716.26 908.59 ;
        RECT  1665.26 145.49 1666.26 908.59 ;
        RECT  1615.26 145.49 1616.26 908.59 ;
        RECT  1565.26 365.33 1566.26 693.07 ;
        RECT  1515.26 365.33 1516.26 693.07 ;
        RECT  1465.26 365.33 1466.26 693.07 ;
        RECT  1415.26 365.33 1416.26 693.07 ;
        RECT  1365.26 365.33 1366.26 693.07 ;
        RECT  1315.26 365.33 1316.26 693.07 ;
        RECT  1265.26 365.09 1266.26 693.31 ;
        RECT  1215.26 365.33 1216.26 693.07 ;
        RECT  1165.26 365.33 1166.26 693.07 ;
        RECT  1115.26 365.33 1116.26 693.07 ;
        RECT  1065.26 365.09 1066.26 693.31 ;
        RECT  1015.26 365.33 1016.26 693.07 ;
        RECT  965.26 365.33 966.26 693.07 ;
        RECT  915.26 365.33 916.26 693.07 ;
        RECT  865.26 365.33 866.26 693.07 ;
        RECT  815.26 365.33 816.26 693.07 ;
        RECT  765.26 365.33 766.26 693.07 ;
        RECT  715.26 365.33 716.26 693.07 ;
        RECT  665.26 365.33 666.26 693.07 ;
        RECT  615.26 365.33 616.26 693.07 ;
        RECT  565.26 365.33 566.26 693.07 ;
        RECT  515.26 365.33 516.26 693.07 ;
        RECT  465.26 365.09 466.26 693.31 ;
        RECT  415.26 365.33 416.26 693.07 ;
        RECT  365.26 365.33 366.26 693.07 ;
        RECT  315.26 365.33 316.26 693.07 ;
        RECT  265.26 365.09 266.26 693.31 ;
        RECT  215.26 365.33 216.26 693.07 ;
        RECT  165.26 365.33 166.26 693.07 ;
        RECT  115.26 365.33 116.26 693.07 ;
        RECT  65.26 365.33 66.26 693.07 ;
        RECT  15.26 365.33 16.26 693.07 ;
    END
  END VPWR
  PIN VGND
    DIRECTION INOUT ;
    USE GROUND ;
    PORT
      LAYER TopMetal1 ;
        RECT  5.76 1030.12 2269.39 1032.12 ;
        RECT  5.76 980.12 2269.39 982.12 ;
        RECT  5.76 930.12 2269.39 932.12 ;
        RECT  5.76 880.12 2269.39 882.12 ;
        RECT  5.76 830.12 2269.39 832.12 ;
        RECT  5.76 780.12 2269.39 782.12 ;
        RECT  5.76 730.12 2269.39 732.12 ;
        RECT  5.76 680.12 2269.39 682.12 ;
        RECT  5.76 630.12 2269.39 632.12 ;
        RECT  5.76 580.12 2269.39 582.12 ;
        RECT  5.76 530.12 2269.39 532.12 ;
        RECT  5.76 480.12 2269.39 482.12 ;
        RECT  5.76 430.12 2269.39 432.12 ;
        RECT  5.76 380.12 2269.39 382.12 ;
        RECT  5.76 330.12 2269.39 332.12 ;
        RECT  5.76 280.12 2269.39 282.12 ;
        RECT  5.76 230.12 2269.39 232.12 ;
        RECT  5.76 180.12 2269.39 182.12 ;
        RECT  5.76 130.12 2269.39 132.12 ;
        RECT  5.76 80.12 2269.39 82.12 ;
        RECT  5.76 30.12 2269.39 32.12 ;
      LAYER Metal4 ;
        RECT  2268.26 14.9 2269.26 1043.5 ;
        RECT  2218.26 14.9 2219.26 1043.5 ;
        RECT  2168.26 145.49 2169.26 908.59 ;
        RECT  2118.26 145.49 2119.26 908.59 ;
        RECT  2068.26 145.25 2069.26 908.83 ;
        RECT  2018.26 145.49 2019.26 908.59 ;
        RECT  1968.26 145.49 1969.26 908.59 ;
        RECT  1918.26 145.49 1919.26 908.59 ;
        RECT  1868.26 145.49 1869.26 908.59 ;
        RECT  1818.26 145.49 1819.26 908.59 ;
        RECT  1768.26 145.49 1769.26 908.59 ;
        RECT  1718.26 145.49 1719.26 908.59 ;
        RECT  1668.26 145.25 1669.26 908.83 ;
        RECT  1618.26 145.25 1619.26 908.83 ;
        RECT  1568.26 365.09 1569.26 693.31 ;
        RECT  1518.26 365.09 1519.26 693.31 ;
        RECT  1468.26 365.33 1469.26 693.07 ;
        RECT  1418.26 365.33 1419.26 693.07 ;
        RECT  1368.26 365.33 1369.26 693.07 ;
        RECT  1318.26 365.33 1319.26 693.07 ;
        RECT  1268.26 365.33 1269.26 693.07 ;
        RECT  1218.26 365.33 1219.26 693.07 ;
        RECT  1168.26 365.33 1169.26 693.07 ;
        RECT  1118.26 365.33 1119.26 693.07 ;
        RECT  1068.26 365.33 1069.26 693.07 ;
        RECT  1018.26 365.33 1019.26 693.07 ;
        RECT  968.26 365.33 969.26 693.07 ;
        RECT  918.26 365.33 919.26 693.07 ;
        RECT  868.26 365.09 869.26 693.31 ;
        RECT  818.26 365.09 819.26 693.31 ;
        RECT  768.26 365.09 769.26 693.31 ;
        RECT  718.26 365.09 719.26 693.31 ;
        RECT  668.26 365.33 669.26 693.07 ;
        RECT  618.26 365.33 619.26 693.07 ;
        RECT  568.26 365.33 569.26 693.07 ;
        RECT  518.26 365.33 519.26 693.07 ;
        RECT  468.26 365.33 469.26 693.07 ;
        RECT  418.26 365.33 419.26 693.07 ;
        RECT  368.26 365.33 369.26 693.07 ;
        RECT  318.26 365.33 319.26 693.07 ;
        RECT  268.26 365.33 269.26 693.07 ;
        RECT  218.26 365.33 219.26 693.07 ;
        RECT  168.26 365.33 169.26 693.07 ;
        RECT  118.26 365.33 119.26 693.07 ;
        RECT  68.26 365.09 69.26 693.31 ;
        RECT  18.26 365.09 19.26 693.31 ;
    END
  END VGND
  OBS
    LAYER Metal1 ;
     RECT  0 14.9 2275 1043.5 ;
    LAYER Metal2 ;
     RECT  0 14.9 2275 1043.5 ;
    LAYER Metal3 ;
     RECT  0 14.9 2275 1043.5 ;
    LAYER Metal4 ;
     RECT  0 14.9 2275 1043.5 ;
    LAYER TopMetal1 ;
     RECT  0 14.9 2275 1043.5 ;
  END
END ino_data_cache
END LIBRARY
